###############################################################
#  Generated by:      Cadence Innovus 23.15-s106_1
#  OS:                Linux x86_64(Host ID ASIC-vm)
#  Generated on:      Fri Nov 14 15:30:56 2025
#  Design:            matmul_sync
#  Command:           write_lef_abstract -exclude_obs_layers $top_layer -stripe_pins -pg_pin_layers 10 [file join models [get_db flow_report_name] [get_db [current_design] .name].lef]
###############################################################

VERSION 5.8 ;

BUSBITCHARS "[]" ;
DIVIDERCHAR "/" ;

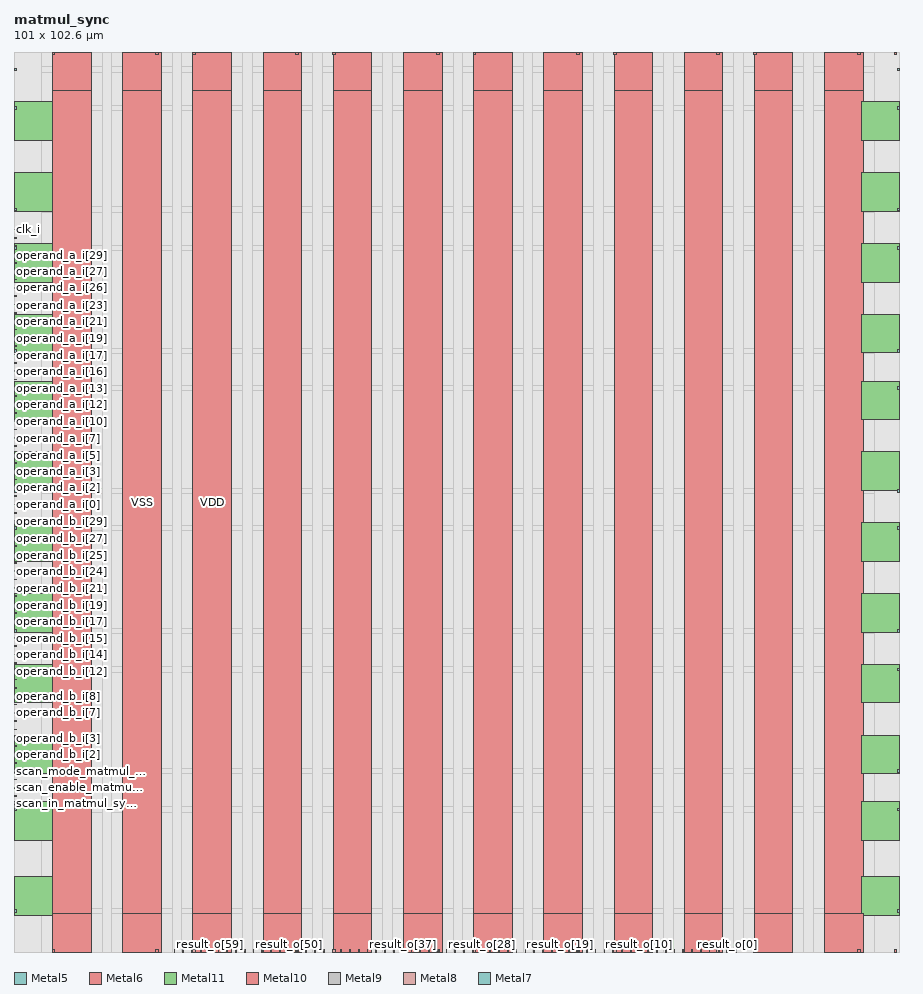
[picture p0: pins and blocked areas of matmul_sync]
MACRO matmul_sync
  CLASS BLOCK ;
  SIZE 101.000000 BY 102.600000 ;
  FOREIGN matmul_sync 0.000000 0.000000 ;
  ORIGIN 0 0 ;
  SYMMETRY X Y R90 ;
  PIN clk_i
    DIRECTION INPUT ;
    USE SIGNAL ;
    ANTENNAPARTIALMETALAREA 0.99075 LAYER Metal5  ;
    ANTENNAPARTIALMETALSIDEAREA 3.5514 LAYER Metal5  ;
    ANTENNAMODEL OXIDE1 ;
    ANTENNAGATEAREA 0.1755 LAYER Metal5  ;
    ANTENNAMAXAREACAR 6.54359 LAYER Metal5  ;
    ANTENNAMAXSIDEAREACAR 25.1726 LAYER Metal5  ;
    ANTENNAMAXCUTCAR 0.451282 LAYER Via5  ;
    PORT
      LAYER Metal5 ;
        RECT 0.000000 82.325000 0.250000 82.405000 ;
    END
  END clk_i
  PIN rst_ni
    DIRECTION INPUT ;
    USE SIGNAL ;
    ANTENNAPARTIALMETALAREA 0.3474 LAYER Metal5  ;
    ANTENNAPARTIALMETALSIDEAREA 1.5318 LAYER Metal5  ;
    ANTENNAMODEL OXIDE1 ;
    ANTENNAGATEAREA 0.0162 LAYER Metal5  ;
    ANTENNAMAXAREACAR 27.3673 LAYER Metal5  ;
    ANTENNAMAXSIDEAREACAR 129.926 LAYER Metal5  ;
    ANTENNAMAXCUTCAR 3.60802 LAYER Via5  ;
    PORT
      LAYER Metal5 ;
        RECT 0.000000 81.375000 0.250000 81.455000 ;
    END
  END rst_ni
  PIN operand_a_i[31]
    DIRECTION INPUT ;
    USE SIGNAL ;
    ANTENNAPARTIALMETALAREA 1.433 LAYER Metal5  ;
    ANTENNAPARTIALMETALSIDEAREA 6.417 LAYER Metal5  ;
    ANTENNAMODEL OXIDE1 ;
    ANTENNAGATEAREA 0.02925 LAYER Metal5  ;
    ANTENNAMAXAREACAR 71.5282 LAYER Metal5  ;
    ANTENNAMAXSIDEAREACAR 326.482 LAYER Metal5  ;
    ANTENNAMAXCUTCAR 2.89915 LAYER Via5  ;
    PORT
      LAYER Metal5 ;
        RECT 0.000000 80.425000 0.250000 80.505000 ;
    END
  END operand_a_i[31]
  PIN operand_a_i[30]
    DIRECTION INPUT ;
    USE SIGNAL ;
    ANTENNAPARTIALMETALAREA 0.9234 LAYER Metal5  ;
    ANTENNAPARTIALMETALSIDEAREA 4.1238 LAYER Metal5  ;
    ANTENNAMODEL OXIDE1 ;
    ANTENNAGATEAREA 0.02925 LAYER Metal5  ;
    ANTENNAMAXAREACAR 39.8085 LAYER Metal5  ;
    ANTENNAMAXSIDEAREACAR 184.821 LAYER Metal5  ;
    ANTENNAMAXCUTCAR 2.89915 LAYER Via5  ;
    PORT
      LAYER Metal5 ;
        RECT 0.000000 79.475000 0.250000 79.555000 ;
    END
  END operand_a_i[30]
  PIN operand_a_i[29]
    DIRECTION INPUT ;
    USE SIGNAL ;
    ANTENNAPARTIALMETALAREA 1.5314 LAYER Metal5  ;
    ANTENNAPARTIALMETALSIDEAREA 6.8598 LAYER Metal5  ;
    ANTENNAMODEL OXIDE1 ;
    ANTENNAGATEAREA 0.02925 LAYER Metal5  ;
    ANTENNAMAXAREACAR 61.135 LAYER Metal5  ;
    ANTENNAMAXSIDEAREACAR 279.713 LAYER Metal5  ;
    ANTENNAMAXCUTCAR 2.89915 LAYER Via5  ;
    PORT
      LAYER Metal5 ;
        RECT 0.000000 78.525000 0.250000 78.605000 ;
    END
  END operand_a_i[29]
  PIN operand_a_i[28]
    DIRECTION INPUT ;
    USE SIGNAL ;
    ANTENNAPARTIALMETALAREA 0.9874 LAYER Metal5  ;
    ANTENNAPARTIALMETALSIDEAREA 4.4118 LAYER Metal5  ;
    ANTENNAMODEL OXIDE1 ;
    ANTENNAGATEAREA 0.02925 LAYER Metal5  ;
    ANTENNAMAXAREACAR 41.4769 LAYER Metal5  ;
    ANTENNAMAXSIDEAREACAR 192.328 LAYER Metal5  ;
    ANTENNAMAXCUTCAR 2.89915 LAYER Via5  ;
    PORT
      LAYER Metal5 ;
        RECT 0.000000 77.575000 0.250000 77.655000 ;
    END
  END operand_a_i[28]
  PIN operand_a_i[27]
    DIRECTION INPUT ;
    USE SIGNAL ;
    ANTENNAPARTIALMETALAREA 1.6274 LAYER Metal5  ;
    ANTENNAPARTIALMETALSIDEAREA 7.2918 LAYER Metal5  ;
    ANTENNAMODEL OXIDE1 ;
    ANTENNAGATEAREA 0.02925 LAYER Metal5  ;
    ANTENNAMAXAREACAR 72.9949 LAYER Metal5  ;
    ANTENNAMAXSIDEAREACAR 331.056 LAYER Metal5  ;
    ANTENNAMAXCUTCAR 2.98462 LAYER Via5  ;
    PORT
      LAYER Metal5 ;
        RECT 0.000000 76.625000 0.250000 76.705000 ;
    END
  END operand_a_i[27]
  PIN operand_a_i[26]
    DIRECTION INPUT ;
    USE SIGNAL ;
    ANTENNAPARTIALMETALAREA 1.7164 LAYER Metal5  ;
    ANTENNAPARTIALMETALSIDEAREA 7.7238 LAYER Metal5  ;
    ANTENNAMODEL OXIDE1 ;
    ANTENNAGATEAREA 0.02925 LAYER Metal5  ;
    ANTENNAMAXAREACAR 64.2872 LAYER Metal5  ;
    ANTENNAMAXSIDEAREACAR 294.974 LAYER Metal5  ;
    ANTENNAMAXCUTCAR 2.89915 LAYER Via5  ;
    PORT
      LAYER Metal5 ;
        RECT 0.000000 75.675000 0.250000 75.755000 ;
    END
  END operand_a_i[26]
  PIN operand_a_i[25]
    DIRECTION INPUT ;
    USE SIGNAL ;
    ANTENNAPARTIALMETALAREA 0.8364 LAYER Metal5  ;
    ANTENNAPARTIALMETALSIDEAREA 3.7638 LAYER Metal5  ;
    ANTENNAMODEL OXIDE1 ;
    ANTENNAGATEAREA 0.02925 LAYER Metal5  ;
    ANTENNAMAXAREACAR 34.1744 LAYER Metal5  ;
    ANTENNAMAXSIDEAREACAR 160.328 LAYER Metal5  ;
    ANTENNAMAXCUTCAR 2.70769 LAYER Via5  ;
    PORT
      LAYER Metal5 ;
        RECT 0.000000 74.725000 0.250000 74.805000 ;
    END
  END operand_a_i[25]
  PIN operand_a_i[24]
    DIRECTION INPUT ;
    USE SIGNAL ;
    ANTENNAPARTIALMETALAREA 0.9554 LAYER Metal5  ;
    ANTENNAPARTIALMETALSIDEAREA 4.2678 LAYER Metal5  ;
    ANTENNAMODEL OXIDE1 ;
    ANTENNAGATEAREA 0.02925 LAYER Metal5  ;
    ANTENNAMAXAREACAR 39.3436 LAYER Metal5  ;
    ANTENNAMAXSIDEAREACAR 182.728 LAYER Metal5  ;
    ANTENNAMAXCUTCAR 2.89915 LAYER Via5  ;
    PORT
      LAYER Metal5 ;
        RECT 0.000000 73.775000 0.250000 73.855000 ;
    END
  END operand_a_i[24]
  PIN operand_a_i[23]
    DIRECTION INPUT ;
    USE SIGNAL ;
    ANTENNAPARTIALMETALAREA 0.7932 LAYER Metal5  ;
    ANTENNAPARTIALMETALSIDEAREA 3.5694 LAYER Metal5  ;
    ANTENNAMODEL OXIDE1 ;
    ANTENNAGATEAREA 0.02925 LAYER Metal5  ;
    ANTENNAMAXAREACAR 47.8974 LAYER Metal5  ;
    ANTENNAMAXSIDEAREACAR 220.144 LAYER Metal5  ;
    ANTENNAMAXCUTCAR 2.73162 LAYER Via5  ;
    PORT
      LAYER Metal5 ;
        RECT 0.000000 72.825000 0.250000 72.905000 ;
    END
  END operand_a_i[23]
  PIN operand_a_i[22]
    DIRECTION INPUT ;
    USE SIGNAL ;
    ANTENNAPARTIALMETALAREA 1.7386 LAYER Metal5  ;
    ANTENNAPARTIALMETALSIDEAREA 7.7922 LAYER Metal5  ;
    ANTENNAMODEL OXIDE1 ;
    ANTENNAGATEAREA 0.02925 LAYER Metal5  ;
    ANTENNAMAXAREACAR 69.2376 LAYER Metal5  ;
    ANTENNAMAXSIDEAREACAR 317.251 LAYER Metal5  ;
    ANTENNAMAXCUTCAR 2.89915 LAYER Via5  ;
    PORT
      LAYER Metal5 ;
        RECT 0.000000 71.875000 0.250000 71.955000 ;
    END
  END operand_a_i[22]
  PIN operand_a_i[21]
    DIRECTION INPUT ;
    USE SIGNAL ;
    ANTENNAPARTIALMETALAREA 1.4034 LAYER Metal5  ;
    ANTENNAPARTIALMETALSIDEAREA 6.2838 LAYER Metal5  ;
    ANTENNAMODEL OXIDE1 ;
    ANTENNAGATEAREA 0.02925 LAYER Metal5  ;
    ANTENNAMAXAREACAR 69.9145 LAYER Metal5  ;
    ANTENNAMAXSIDEAREACAR 319.221 LAYER Metal5  ;
    ANTENNAMAXCUTCAR 2.89915 LAYER Via5  ;
    PORT
      LAYER Metal5 ;
        RECT 0.000000 70.925000 0.250000 71.005000 ;
    END
  END operand_a_i[21]
  PIN operand_a_i[20]
    DIRECTION INPUT ;
    USE SIGNAL ;
    ANTENNAPARTIALMETALAREA 1.8602 LAYER Metal5  ;
    ANTENNAPARTIALMETALSIDEAREA 8.3394 LAYER Metal5  ;
    ANTENNAMODEL OXIDE1 ;
    ANTENNAGATEAREA 0.02925 LAYER Metal5  ;
    ANTENNAMAXAREACAR 68.0615 LAYER Metal5  ;
    ANTENNAMAXSIDEAREACAR 311.959 LAYER Metal5  ;
    ANTENNAMAXCUTCAR 2.89915 LAYER Via5  ;
    PORT
      LAYER Metal5 ;
        RECT 0.000000 69.975000 0.250000 70.055000 ;
    END
  END operand_a_i[20]
  PIN operand_a_i[19]
    DIRECTION INPUT ;
    USE SIGNAL ;
    ANTENNAPARTIALMETALAREA 1.5434 LAYER Metal5  ;
    ANTENNAPARTIALMETALSIDEAREA 6.9138 LAYER Metal5  ;
    ANTENNAMODEL OXIDE1 ;
    ANTENNAGATEAREA 0.02925 LAYER Metal5  ;
    ANTENNAMAXAREACAR 72.5128 LAYER Metal5  ;
    ANTENNAMAXSIDEAREACAR 330.913 LAYER Metal5  ;
    ANTENNAMAXCUTCAR 2.89915 LAYER Via5  ;
    PORT
      LAYER Metal5 ;
        RECT 0.000000 69.025000 0.250000 69.105000 ;
    END
  END operand_a_i[19]
  PIN operand_a_i[18]
    DIRECTION INPUT ;
    USE SIGNAL ;
    ANTENNAPARTIALMETALAREA 1.4026 LAYER Metal5  ;
    ANTENNAPARTIALMETALSIDEAREA 6.2802 LAYER Metal5  ;
    ANTENNAMODEL OXIDE1 ;
    ANTENNAGATEAREA 0.02925 LAYER Metal5  ;
    ANTENNAMAXAREACAR 70.4342 LAYER Metal5  ;
    ANTENNAMAXSIDEAREACAR 321.559 LAYER Metal5  ;
    ANTENNAMAXCUTCAR 2.89915 LAYER Via5  ;
    PORT
      LAYER Metal5 ;
        RECT 0.000000 68.075000 0.250000 68.155000 ;
    END
  END operand_a_i[18]
  PIN operand_a_i[17]
    DIRECTION INPUT ;
    USE SIGNAL ;
    ANTENNAPARTIALMETALAREA 0.8594 LAYER Metal5  ;
    ANTENNAPARTIALMETALSIDEAREA 3.8358 LAYER Metal5  ;
    ANTENNAMODEL OXIDE1 ;
    ANTENNAGATEAREA 0.02925 LAYER Metal5  ;
    ANTENNAMAXAREACAR 49.9692 LAYER Metal5  ;
    ANTENNAMAXSIDEAREACAR 231.405 LAYER Metal5  ;
    ANTENNAMAXCUTCAR 2.54017 LAYER Via5  ;
    PORT
      LAYER Metal5 ;
        RECT 0.000000 67.125000 0.250000 67.205000 ;
    END
  END operand_a_i[17]
  PIN operand_a_i[16]
    DIRECTION INPUT ;
    USE SIGNAL ;
    ANTENNAPARTIALMETALAREA 0.1874 LAYER Metal5  ;
    ANTENNAPARTIALMETALSIDEAREA 0.8118 LAYER Metal5  ;
    ANTENNAMODEL OXIDE1 ;
    ANTENNAGATEAREA 0.02925 LAYER Metal5  ;
    ANTENNAMAXAREACAR 39.8291 LAYER Metal5  ;
    ANTENNAMAXSIDEAREACAR 183.836 LAYER Metal5  ;
    ANTENNAMAXCUTCAR 2.89915 LAYER Via5  ;
    PORT
      LAYER Metal5 ;
        RECT 0.000000 66.175000 0.250000 66.255000 ;
    END
  END operand_a_i[16]
  PIN operand_a_i[15]
    DIRECTION INPUT ;
    USE SIGNAL ;
    ANTENNAPARTIALMETALAREA 0.8684 LAYER Metal5  ;
    ANTENNAPARTIALMETALSIDEAREA 3.9078 LAYER Metal5  ;
    ANTENNAMODEL OXIDE1 ;
    ANTENNAGATEAREA 0.02925 LAYER Metal5  ;
    ANTENNAMAXAREACAR 50.5573 LAYER Metal5  ;
    ANTENNAMAXSIDEAREACAR 233.19 LAYER Metal5  ;
    ANTENNAMAXCUTCAR 2.89915 LAYER Via5  ;
    PORT
      LAYER Metal5 ;
        RECT 0.000000 65.225000 0.250000 65.305000 ;
    END
  END operand_a_i[15]
  PIN operand_a_i[14]
    DIRECTION INPUT ;
    USE SIGNAL ;
    ANTENNAPARTIALMETALAREA 1.4826 LAYER Metal5  ;
    ANTENNAPARTIALMETALSIDEAREA 6.6402 LAYER Metal5  ;
    ANTENNAMODEL OXIDE1 ;
    ANTENNAGATEAREA 0.02925 LAYER Metal5  ;
    ANTENNAMAXAREACAR 92.5607 LAYER Metal5  ;
    ANTENNAMAXSIDEAREACAR 421.128 LAYER Metal5  ;
    ANTENNAMAXCUTCAR 2.89915 LAYER Via5  ;
    PORT
      LAYER Metal5 ;
        RECT 0.000000 64.275000 0.250000 64.355000 ;
    END
  END operand_a_i[14]
  PIN operand_a_i[13]
    DIRECTION INPUT ;
    USE SIGNAL ;
    ANTENNAPARTIALMETALAREA 1.5618 LAYER Metal5  ;
    ANTENNAPARTIALMETALSIDEAREA 6.9966 LAYER Metal5  ;
    ANTENNAMODEL OXIDE1 ;
    ANTENNAGATEAREA 0.02925 LAYER Metal5  ;
    ANTENNAMAXAREACAR 85.9692 LAYER Metal5  ;
    ANTENNAMAXSIDEAREACAR 391.467 LAYER Metal5  ;
    ANTENNAMAXCUTCAR 2.89915 LAYER Via5  ;
    PORT
      LAYER Metal5 ;
        RECT 0.000000 63.325000 0.250000 63.405000 ;
    END
  END operand_a_i[13]
  PIN operand_a_i[12]
    DIRECTION INPUT ;
    USE SIGNAL ;
    ANTENNAPARTIALMETALAREA 0.2354 LAYER Metal5  ;
    ANTENNAPARTIALMETALSIDEAREA 1.0278 LAYER Metal5  ;
    ANTENNAMODEL OXIDE1 ;
    ANTENNAGATEAREA 0.02925 LAYER Metal5  ;
    ANTENNAMAXAREACAR 51.9179 LAYER Metal5  ;
    ANTENNAMAXSIDEAREACAR 238.236 LAYER Metal5  ;
    ANTENNAMAXCUTCAR 2.89915 LAYER Via5  ;
    PORT
      LAYER Metal5 ;
        RECT 0.000000 62.375000 0.250000 62.455000 ;
    END
  END operand_a_i[12]
  PIN operand_a_i[11]
    DIRECTION INPUT ;
    USE SIGNAL ;
    ANTENNAPARTIALMETALAREA 0.8274 LAYER Metal5  ;
    ANTENNAPARTIALMETALSIDEAREA 3.6918 LAYER Metal5  ;
    ANTENNAMODEL OXIDE1 ;
    ANTENNAGATEAREA 0.02925 LAYER Metal5  ;
    ANTENNAMAXAREACAR 50.7692 LAYER Metal5  ;
    ANTENNAMAXSIDEAREACAR 233.067 LAYER Metal5  ;
    ANTENNAMAXCUTCAR 2.89915 LAYER Via5  ;
    PORT
      LAYER Metal5 ;
        RECT 0.000000 61.425000 0.250000 61.505000 ;
    END
  END operand_a_i[11]
  PIN operand_a_i[10]
    DIRECTION INPUT ;
    USE SIGNAL ;
    ANTENNAPARTIALMETALAREA 0.8892 LAYER Metal5  ;
    ANTENNAPARTIALMETALSIDEAREA 4.0014 LAYER Metal5  ;
    ANTENNAMODEL OXIDE1 ;
    ANTENNAGATEAREA 0.02925 LAYER Metal5  ;
    ANTENNAMAXAREACAR 38.9949 LAYER Metal5  ;
    ANTENNAMAXSIDEAREACAR 180.082 LAYER Metal5  ;
    ANTENNAMAXCUTCAR 2.73162 LAYER Via5  ;
    PORT
      LAYER Metal5 ;
        RECT 0.000000 60.475000 0.250000 60.555000 ;
    END
  END operand_a_i[10]
  PIN operand_a_i[9]
    DIRECTION INPUT ;
    USE SIGNAL ;
    ANTENNAPARTIALMETALAREA 1.3714 LAYER Metal5  ;
    ANTENNAPARTIALMETALSIDEAREA 6.1398 LAYER Metal5  ;
    ANTENNAMODEL OXIDE1 ;
    ANTENNAGATEAREA 0.02925 LAYER Metal5  ;
    ANTENNAMAXAREACAR 59.6581 LAYER Metal5  ;
    ANTENNAMAXSIDEAREACAR 273.067 LAYER Metal5  ;
    ANTENNAMAXCUTCAR 2.89915 LAYER Via5  ;
    PORT
      LAYER Metal5 ;
        RECT 0.000000 59.525000 0.250000 59.605000 ;
    END
  END operand_a_i[9]
  PIN operand_a_i[8]
    DIRECTION INPUT ;
    USE SIGNAL ;
    ANTENNAPARTIALMETALAREA 1.9116 LAYER Metal5  ;
    ANTENNAPARTIALMETALSIDEAREA 8.6022 LAYER Metal5  ;
    ANTENNAMODEL OXIDE1 ;
    ANTENNAGATEAREA 0.02925 LAYER Metal5  ;
    ANTENNAMAXAREACAR 71.7744 LAYER Metal5  ;
    ANTENNAMAXSIDEAREACAR 327.59 LAYER Metal5  ;
    ANTENNAMAXCUTCAR 2.89915 LAYER Via5  ;
    PORT
      LAYER Metal5 ;
        RECT 0.000000 58.575000 0.250000 58.655000 ;
    END
  END operand_a_i[8]
  PIN operand_a_i[7]
    DIRECTION INPUT ;
    USE SIGNAL ;
    ANTENNAPARTIALMETALAREA 2.3154 LAYER Metal5  ;
    ANTENNAPARTIALMETALSIDEAREA 10.3878 LAYER Metal5  ;
    ANTENNAMODEL OXIDE1 ;
    ANTENNAGATEAREA 0.02925 LAYER Metal5  ;
    ANTENNAMAXAREACAR 91.0359 LAYER Metal5  ;
    ANTENNAMAXSIDEAREACAR 415.344 LAYER Metal5  ;
    ANTENNAMAXCUTCAR 2.89915 LAYER Via5  ;
    PORT
      LAYER Metal5 ;
        RECT 0.000000 57.625000 0.250000 57.705000 ;
    END
  END operand_a_i[7]
  PIN operand_a_i[6]
    DIRECTION INPUT ;
    USE SIGNAL ;
    ANTENNAPARTIALMETALAREA 2.2034 LAYER Metal5  ;
    ANTENNAPARTIALMETALSIDEAREA 9.8838 LAYER Metal5  ;
    ANTENNAMODEL OXIDE1 ;
    ANTENNAGATEAREA 0.02925 LAYER Metal5  ;
    ANTENNAMAXAREACAR 96.7453 LAYER Metal5  ;
    ANTENNAMAXSIDEAREACAR 439.959 LAYER Metal5  ;
    ANTENNAMAXCUTCAR 2.89915 LAYER Via5  ;
    PORT
      LAYER Metal5 ;
        RECT 0.000000 56.675000 0.250000 56.755000 ;
    END
  END operand_a_i[6]
  PIN operand_a_i[5]
    DIRECTION INPUT ;
    USE SIGNAL ;
    ANTENNAPARTIALMETALAREA 1.5634 LAYER Metal5  ;
    ANTENNAPARTIALMETALSIDEAREA 7.0038 LAYER Metal5  ;
    ANTENNAMODEL OXIDE1 ;
    ANTENNAGATEAREA 0.02925 LAYER Metal5  ;
    ANTENNAMAXAREACAR 80.9709 LAYER Metal5  ;
    ANTENNAMAXSIDEAREACAR 370.051 LAYER Metal5  ;
    ANTENNAMAXCUTCAR 2.89915 LAYER Via5  ;
    PORT
      LAYER Metal5 ;
        RECT 0.000000 55.725000 0.250000 55.805000 ;
    END
  END operand_a_i[5]
  PIN operand_a_i[4]
    DIRECTION INPUT ;
    USE SIGNAL ;
    ANTENNAPARTIALMETALAREA 2.1066 LAYER Metal5  ;
    ANTENNAPARTIALMETALSIDEAREA 9.4482 LAYER Metal5  ;
    ANTENNAMODEL OXIDE1 ;
    ANTENNAGATEAREA 0.02925 LAYER Metal5  ;
    ANTENNAMAXAREACAR 85.641 LAYER Metal5  ;
    ANTENNAMAXSIDEAREACAR 389.99 LAYER Metal5  ;
    ANTENNAMAXCUTCAR 2.89915 LAYER Via5  ;
    PORT
      LAYER Metal5 ;
        RECT 0.000000 54.775000 0.250000 54.855000 ;
    END
  END operand_a_i[4]
  PIN operand_a_i[3]
    DIRECTION INPUT ;
    USE SIGNAL ;
    ANTENNAPARTIALMETALAREA 2.0242 LAYER Metal5  ;
    ANTENNAPARTIALMETALSIDEAREA 9.0774 LAYER Metal5  ;
    ANTENNAMODEL OXIDE1 ;
    ANTENNAGATEAREA 0.02925 LAYER Metal5  ;
    ANTENNAMAXAREACAR 79.2308 LAYER Metal5  ;
    ANTENNAMAXSIDEAREACAR 359.118 LAYER Metal5  ;
    ANTENNAMAXCUTCAR 2.98462 LAYER Via5  ;
    PORT
      LAYER Metal5 ;
        RECT 0.000000 53.825000 0.250000 53.905000 ;
    END
  END operand_a_i[3]
  PIN operand_a_i[2]
    DIRECTION INPUT ;
    USE SIGNAL ;
    ANTENNAPARTIALMETALAREA 2.0242 LAYER Metal5  ;
    ANTENNAPARTIALMETALSIDEAREA 9.0774 LAYER Metal5  ;
    ANTENNAMODEL OXIDE1 ;
    ANTENNAGATEAREA 0.02925 LAYER Metal5  ;
    ANTENNAMAXAREACAR 77.135 LAYER Metal5  ;
    ANTENNAMAXSIDEAREACAR 351.713 LAYER Metal5  ;
    ANTENNAMAXCUTCAR 2.89915 LAYER Via5  ;
    PORT
      LAYER Metal5 ;
        RECT 0.000000 52.875000 0.250000 52.955000 ;
    END
  END operand_a_i[2]
  PIN operand_a_i[1]
    DIRECTION INPUT ;
    USE SIGNAL ;
    ANTENNAPARTIALMETALAREA 1.4756 LAYER Metal5  ;
    ANTENNAPARTIALMETALSIDEAREA 6.6402 LAYER Metal5  ;
    ANTENNAMODEL OXIDE1 ;
    ANTENNAGATEAREA 0.02925 LAYER Metal5  ;
    ANTENNAMAXAREACAR 55.0291 LAYER Metal5  ;
    ANTENNAMAXSIDEAREACAR 254.174 LAYER Metal5  ;
    ANTENNAMAXCUTCAR 2.54017 LAYER Via5  ;
    PORT
      LAYER Metal5 ;
        RECT 0.000000 51.925000 0.250000 52.005000 ;
    END
  END operand_a_i[1]
  PIN operand_a_i[0]
    DIRECTION INPUT ;
    USE SIGNAL ;
    ANTENNAPARTIALMETALAREA 0.1874 LAYER Metal5  ;
    ANTENNAPARTIALMETALSIDEAREA 0.8118 LAYER Metal5  ;
    ANTENNAMODEL OXIDE1 ;
    ANTENNAGATEAREA 0.02925 LAYER Metal5  ;
    ANTENNAMAXAREACAR 41.388 LAYER Metal5  ;
    ANTENNAMAXSIDEAREACAR 190.851 LAYER Metal5  ;
    ANTENNAMAXCUTCAR 2.89915 LAYER Via5  ;
    PORT
      LAYER Metal5 ;
        RECT 0.000000 50.975000 0.250000 51.055000 ;
    END
  END operand_a_i[0]
  PIN operand_b_i[31]
    DIRECTION INPUT ;
    USE SIGNAL ;
    ANTENNAPARTIALMETALAREA 0.9874 LAYER Metal5  ;
    ANTENNAPARTIALMETALSIDEAREA 4.4118 LAYER Metal5  ;
    ANTENNAMODEL OXIDE1 ;
    ANTENNAGATEAREA 0.02925 LAYER Metal5  ;
    ANTENNAMAXAREACAR 92.6154 LAYER Metal5  ;
    ANTENNAMAXSIDEAREACAR 421.374 LAYER Metal5  ;
    ANTENNAMAXCUTCAR 2.89915 LAYER Via5  ;
    PORT
      LAYER Metal5 ;
        RECT 0.000000 50.025000 0.250000 50.105000 ;
    END
  END operand_b_i[31]
  PIN operand_b_i[30]
    DIRECTION INPUT ;
    USE SIGNAL ;
    ANTENNAPARTIALMETALAREA 0.9074 LAYER Metal5  ;
    ANTENNAPARTIALMETALSIDEAREA 4.0518 LAYER Metal5  ;
    ANTENNAMODEL OXIDE1 ;
    ANTENNAGATEAREA 0.02925 LAYER Metal5  ;
    ANTENNAMAXAREACAR 39.6444 LAYER Metal5  ;
    ANTENNAMAXSIDEAREACAR 184.082 LAYER Metal5  ;
    ANTENNAMAXCUTCAR 2.89915 LAYER Via5  ;
    PORT
      LAYER Metal5 ;
        RECT 0.000000 49.075000 0.250000 49.155000 ;
    END
  END operand_b_i[30]
  PIN operand_b_i[29]
    DIRECTION INPUT ;
    USE SIGNAL ;
    ANTENNAPARTIALMETALAREA 0.2354 LAYER Metal5  ;
    ANTENNAPARTIALMETALSIDEAREA 1.0278 LAYER Metal5  ;
    ANTENNAMODEL OXIDE1 ;
    ANTENNAGATEAREA 0.02925 LAYER Metal5  ;
    ANTENNAMAXAREACAR 45.0256 LAYER Metal5  ;
    ANTENNAMAXSIDEAREACAR 207.221 LAYER Metal5  ;
    ANTENNAMAXCUTCAR 2.89915 LAYER Via5  ;
    PORT
      LAYER Metal5 ;
        RECT 0.000000 48.125000 0.250000 48.205000 ;
    END
  END operand_b_i[29]
  PIN operand_b_i[28]
    DIRECTION INPUT ;
    USE SIGNAL ;
    ANTENNAPARTIALMETALAREA 1.5778 LAYER Metal5  ;
    ANTENNAPARTIALMETALSIDEAREA 7.0686 LAYER Metal5  ;
    ANTENNAMODEL OXIDE1 ;
    ANTENNAGATEAREA 0.02925 LAYER Metal5  ;
    ANTENNAMAXAREACAR 98.5846 LAYER Metal5  ;
    ANTENNAMAXSIDEAREACAR 449.313 LAYER Metal5  ;
    ANTENNAMAXCUTCAR 2.89915 LAYER Via5  ;
    PORT
      LAYER Metal5 ;
        RECT 0.000000 47.175000 0.250000 47.255000 ;
    END
  END operand_b_i[28]
  PIN operand_b_i[27]
    DIRECTION INPUT ;
    USE SIGNAL ;
    ANTENNAPARTIALMETALAREA 1.6266 LAYER Metal5  ;
    ANTENNAPARTIALMETALSIDEAREA 7.2882 LAYER Metal5  ;
    ANTENNAMODEL OXIDE1 ;
    ANTENNAGATEAREA 0.02925 LAYER Metal5  ;
    ANTENNAMAXAREACAR 64.0615 LAYER Metal5  ;
    ANTENNAMAXSIDEAREACAR 292.882 LAYER Metal5  ;
    ANTENNAMAXCUTCAR 2.89915 LAYER Via5  ;
    PORT
      LAYER Metal5 ;
        RECT 0.000000 46.225000 0.250000 46.305000 ;
    END
  END operand_b_i[27]
  PIN operand_b_i[26]
    DIRECTION INPUT ;
    USE SIGNAL ;
    ANTENNAPARTIALMETALAREA 1.9932 LAYER Metal5  ;
    ANTENNAPARTIALMETALSIDEAREA 8.9694 LAYER Metal5  ;
    ANTENNAMODEL OXIDE1 ;
    ANTENNAGATEAREA 0.02925 LAYER Metal5  ;
    ANTENNAMAXAREACAR 88.4718 LAYER Metal5  ;
    ANTENNAMAXSIDEAREACAR 402.728 LAYER Metal5  ;
    ANTENNAMAXCUTCAR 2.73162 LAYER Via5  ;
    PORT
      LAYER Metal5 ;
        RECT 0.000000 45.275000 0.250000 45.355000 ;
    END
  END operand_b_i[26]
  PIN operand_b_i[25]
    DIRECTION INPUT ;
    USE SIGNAL ;
    ANTENNAPARTIALMETALAREA 1.6754 LAYER Metal5  ;
    ANTENNAPARTIALMETALSIDEAREA 7.5078 LAYER Metal5  ;
    ANTENNAMODEL OXIDE1 ;
    ANTENNAGATEAREA 0.02925 LAYER Metal5  ;
    ANTENNAMAXAREACAR 62.9197 LAYER Metal5  ;
    ANTENNAMAXSIDEAREACAR 288.821 LAYER Metal5  ;
    ANTENNAMAXCUTCAR 2.89915 LAYER Via5  ;
    PORT
      LAYER Metal5 ;
        RECT 0.000000 44.325000 0.250000 44.405000 ;
    END
  END operand_b_i[25]
  PIN operand_b_i[24]
    DIRECTION INPUT ;
    USE SIGNAL ;
    ANTENNAPARTIALMETALAREA 1.6754 LAYER Metal5  ;
    ANTENNAPARTIALMETALSIDEAREA 7.5078 LAYER Metal5  ;
    ANTENNAMODEL OXIDE1 ;
    ANTENNAGATEAREA 0.02925 LAYER Metal5  ;
    ANTENNAMAXAREACAR 64.9983 LAYER Metal5  ;
    ANTENNAMAXSIDEAREACAR 298.174 LAYER Metal5  ;
    ANTENNAMAXCUTCAR 2.89915 LAYER Via5  ;
    PORT
      LAYER Metal5 ;
        RECT 0.000000 43.375000 0.250000 43.455000 ;
    END
  END operand_b_i[24]
  PIN operand_b_i[23]
    DIRECTION INPUT ;
    USE SIGNAL ;
    ANTENNAPARTIALMETALAREA 0.6994 LAYER Metal5  ;
    ANTENNAPARTIALMETALSIDEAREA 3.1158 LAYER Metal5  ;
    ANTENNAMODEL OXIDE1 ;
    ANTENNAGATEAREA 0.02925 LAYER Metal5  ;
    ANTENNAMAXAREACAR 72.5675 LAYER Metal5  ;
    ANTENNAMAXSIDEAREACAR 331.159 LAYER Metal5  ;
    ANTENNAMAXCUTCAR 2.89915 LAYER Via5  ;
    PORT
      LAYER Metal5 ;
        RECT 0.000000 42.425000 0.250000 42.505000 ;
    END
  END operand_b_i[23]
  PIN operand_b_i[22]
    DIRECTION INPUT ;
    USE SIGNAL ;
    ANTENNAPARTIALMETALAREA 1.721 LAYER Metal5  ;
    ANTENNAPARTIALMETALSIDEAREA 7.713 LAYER Metal5  ;
    ANTENNAMODEL OXIDE1 ;
    ANTENNAGATEAREA 0.02925 LAYER Metal5  ;
    ANTENNAMAXAREACAR 64.4786 LAYER Metal5  ;
    ANTENNAMAXSIDEAREACAR 295.836 LAYER Metal5  ;
    ANTENNAMAXCUTCAR 2.89915 LAYER Via5  ;
    PORT
      LAYER Metal5 ;
        RECT 0.000000 41.475000 0.250000 41.555000 ;
    END
  END operand_b_i[22]
  PIN operand_b_i[21]
    DIRECTION INPUT ;
    USE SIGNAL ;
    ANTENNAPARTIALMETALAREA 1.6898 LAYER Metal5  ;
    ANTENNAPARTIALMETALSIDEAREA 7.5726 LAYER Metal5  ;
    ANTENNAMODEL OXIDE1 ;
    ANTENNAGATEAREA 0.02925 LAYER Metal5  ;
    ANTENNAMAXAREACAR 66.0103 LAYER Metal5  ;
    ANTENNAMAXSIDEAREACAR 302.728 LAYER Metal5  ;
    ANTENNAMAXCUTCAR 2.89915 LAYER Via5  ;
    PORT
      LAYER Metal5 ;
        RECT 0.000000 40.525000 0.250000 40.605000 ;
    END
  END operand_b_i[21]
  PIN operand_b_i[20]
    DIRECTION INPUT ;
    USE SIGNAL ;
    ANTENNAPARTIALMETALAREA 0.9394 LAYER Metal5  ;
    ANTENNAPARTIALMETALSIDEAREA 4.1958 LAYER Metal5  ;
    ANTENNAMODEL OXIDE1 ;
    ANTENNAGATEAREA 0.02925 LAYER Metal5  ;
    ANTENNAMAXAREACAR 57.8872 LAYER Metal5  ;
    ANTENNAMAXSIDEAREACAR 266.174 LAYER Metal5  ;
    ANTENNAMAXCUTCAR 2.89915 LAYER Via5  ;
    PORT
      LAYER Metal5 ;
        RECT 0.000000 39.575000 0.250000 39.655000 ;
    END
  END operand_b_i[20]
  PIN operand_b_i[19]
    DIRECTION INPUT ;
    USE SIGNAL ;
    ANTENNAPARTIALMETALAREA 1.3874 LAYER Metal5  ;
    ANTENNAPARTIALMETALSIDEAREA 6.2118 LAYER Metal5  ;
    ANTENNAMODEL OXIDE1 ;
    ANTENNAGATEAREA 0.02925 LAYER Metal5  ;
    ANTENNAMAXAREACAR 66.1128 LAYER Metal5  ;
    ANTENNAMAXSIDEAREACAR 302.113 LAYER Metal5  ;
    ANTENNAMAXCUTCAR 2.89915 LAYER Via5  ;
    PORT
      LAYER Metal5 ;
        RECT 0.000000 38.625000 0.250000 38.705000 ;
    END
  END operand_b_i[19]
  PIN operand_b_i[18]
    DIRECTION INPUT ;
    USE SIGNAL ;
    ANTENNAPARTIALMETALAREA 1.6266 LAYER Metal5  ;
    ANTENNAPARTIALMETALSIDEAREA 7.2882 LAYER Metal5  ;
    ANTENNAMODEL OXIDE1 ;
    ANTENNAGATEAREA 0.02925 LAYER Metal5  ;
    ANTENNAMAXAREACAR 72.0821 LAYER Metal5  ;
    ANTENNAMAXSIDEAREACAR 330.051 LAYER Metal5  ;
    ANTENNAMAXCUTCAR 2.89915 LAYER Via5  ;
    PORT
      LAYER Metal5 ;
        RECT 0.000000 37.675000 0.250000 37.755000 ;
    END
  END operand_b_i[18]
  PIN operand_b_i[17]
    DIRECTION INPUT ;
    USE SIGNAL ;
    ANTENNAPARTIALMETALAREA 0.9386 LAYER Metal5  ;
    ANTENNAPARTIALMETALSIDEAREA 4.1922 LAYER Metal5  ;
    ANTENNAMODEL OXIDE1 ;
    ANTENNAGATEAREA 0.02925 LAYER Metal5  ;
    ANTENNAMAXAREACAR 37.7231 LAYER Metal5  ;
    ANTENNAMAXSIDEAREACAR 174.359 LAYER Metal5  ;
    ANTENNAMAXCUTCAR 2.89915 LAYER Via5  ;
    PORT
      LAYER Metal5 ;
        RECT 0.000000 36.725000 0.250000 36.805000 ;
    END
  END operand_b_i[17]
  PIN operand_b_i[16]
    DIRECTION INPUT ;
    USE SIGNAL ;
    ANTENNAPARTIALMETALAREA 0.1692 LAYER Metal5  ;
    ANTENNAPARTIALMETALSIDEAREA 0.7614 LAYER Metal5  ;
    ANTENNAMODEL OXIDE1 ;
    ANTENNAGATEAREA 0.02925 LAYER Metal5  ;
    ANTENNAMAXAREACAR 45.5179 LAYER Metal5  ;
    ANTENNAMAXSIDEAREACAR 209.436 LAYER Metal5  ;
    ANTENNAMAXCUTCAR 2.73162 LAYER Via5  ;
    PORT
      LAYER Metal5 ;
        RECT 0.000000 35.775000 0.250000 35.855000 ;
    END
  END operand_b_i[16]
  PIN operand_b_i[15]
    DIRECTION INPUT ;
    USE SIGNAL ;
    ANTENNAPARTIALMETALAREA 0.7474 LAYER Metal5  ;
    ANTENNAPARTIALMETALSIDEAREA 3.3318 LAYER Metal5  ;
    ANTENNAMODEL OXIDE1 ;
    ANTENNAGATEAREA 0.02925 LAYER Metal5  ;
    ANTENNAMAXAREACAR 93.094 LAYER Metal5  ;
    ANTENNAMAXSIDEAREACAR 424.39 LAYER Metal5  ;
    ANTENNAMAXCUTCAR 2.54017 LAYER Via5  ;
    PORT
      LAYER Metal5 ;
        RECT 0.000000 34.825000 0.250000 34.905000 ;
    END
  END operand_b_i[15]
  PIN operand_b_i[14]
    DIRECTION INPUT ;
    USE SIGNAL ;
    ANTENNAPARTIALMETALAREA 0.7954 LAYER Metal5  ;
    ANTENNAPARTIALMETALSIDEAREA 3.5478 LAYER Metal5  ;
    ANTENNAMODEL OXIDE1 ;
    ANTENNAGATEAREA 0.0162 LAYER Metal5  ;
    ANTENNAMAXAREACAR 162.963 LAYER Metal5  ;
    ANTENNAMAXSIDEAREACAR 745.148 LAYER Metal5  ;
    ANTENNAMAXCUTCAR 4.58642 LAYER Via5  ;
    PORT
      LAYER Metal5 ;
        RECT 0.000000 33.875000 0.250000 33.955000 ;
    END
  END operand_b_i[14]
  PIN operand_b_i[13]
    DIRECTION INPUT ;
    USE SIGNAL ;
    ANTENNAPARTIALMETALAREA 1.4674 LAYER Metal5  ;
    ANTENNAPARTIALMETALSIDEAREA 6.5718 LAYER Metal5  ;
    ANTENNAMODEL OXIDE1 ;
    ANTENNAGATEAREA 0.02925 LAYER Metal5  ;
    ANTENNAMAXAREACAR 103.501 LAYER Metal5  ;
    ANTENNAMAXSIDEAREACAR 470.359 LAYER Metal5  ;
    ANTENNAMAXCUTCAR 2.89915 LAYER Via5  ;
    PORT
      LAYER Metal5 ;
        RECT 0.000000 32.925000 0.250000 33.005000 ;
    END
  END operand_b_i[13]
  PIN operand_b_i[12]
    DIRECTION INPUT ;
    USE SIGNAL ;
    ANTENNAPARTIALMETALAREA 0.5476 LAYER Metal5  ;
    ANTENNAPARTIALMETALSIDEAREA 2.4642 LAYER Metal5  ;
    ANTENNAMODEL OXIDE1 ;
    ANTENNAGATEAREA 0.0162 LAYER Metal5  ;
    ANTENNAMAXAREACAR 121.185 LAYER Metal5  ;
    ANTENNAMAXSIDEAREACAR 557.148 LAYER Metal5  ;
    ANTENNAMAXCUTCAR 4.58642 LAYER Via5  ;
    PORT
      LAYER Metal5 ;
        RECT 0.000000 31.975000 0.250000 32.055000 ;
    END
  END operand_b_i[12]
  PIN operand_b_i[11]
    DIRECTION INPUT ;
    USE SIGNAL ;
    ANTENNAPARTIALMETALAREA 0.9074 LAYER Metal5  ;
    ANTENNAPARTIALMETALSIDEAREA 4.0518 LAYER Metal5  ;
    ANTENNAMODEL OXIDE1 ;
    ANTENNAGATEAREA 0.02925 LAYER Metal5  ;
    ANTENNAMAXAREACAR 76.3692 LAYER Metal5  ;
    ANTENNAMAXSIDEAREACAR 348.267 LAYER Metal5  ;
    ANTENNAMAXCUTCAR 2.89915 LAYER Via5  ;
    PORT
      LAYER Metal5 ;
        RECT 0.000000 31.025000 0.250000 31.105000 ;
    END
  END operand_b_i[11]
  PIN operand_b_i[10]
    DIRECTION INPUT ;
    USE SIGNAL ;
    ANTENNAPARTIALMETALAREA 0.9714 LAYER Metal5  ;
    ANTENNAPARTIALMETALSIDEAREA 4.3398 LAYER Metal5  ;
    ANTENNAMODEL OXIDE1 ;
    ANTENNAGATEAREA 0.02925 LAYER Metal5  ;
    ANTENNAMAXAREACAR 76.4786 LAYER Metal5  ;
    ANTENNAMAXSIDEAREACAR 348.759 LAYER Metal5  ;
    ANTENNAMAXCUTCAR 2.89915 LAYER Via5  ;
    PORT
      LAYER Metal5 ;
        RECT 0.000000 30.075000 0.250000 30.155000 ;
    END
  END operand_b_i[10]
  PIN operand_b_i[9]
    DIRECTION INPUT ;
    USE SIGNAL ;
    ANTENNAPARTIALMETALAREA 1.0506 LAYER Metal5  ;
    ANTENNAPARTIALMETALSIDEAREA 4.6962 LAYER Metal5  ;
    ANTENNAMODEL OXIDE1 ;
    ANTENNAGATEAREA 0.02925 LAYER Metal5  ;
    ANTENNAMAXAREACAR 78.2291 LAYER Metal5  ;
    ANTENNAMAXSIDEAREACAR 356.636 LAYER Metal5  ;
    ANTENNAMAXCUTCAR 2.89915 LAYER Via5  ;
    PORT
      LAYER Metal5 ;
        RECT 0.000000 29.125000 0.250000 29.205000 ;
    END
  END operand_b_i[9]
  PIN operand_b_i[8]
    DIRECTION INPUT ;
    USE SIGNAL ;
    ANTENNAPARTIALMETALAREA 1.0034 LAYER Metal5  ;
    ANTENNAPARTIALMETALSIDEAREA 4.4838 LAYER Metal5  ;
    ANTENNAMODEL OXIDE1 ;
    ANTENNAGATEAREA 0.02925 LAYER Metal5  ;
    ANTENNAMAXAREACAR 68.7385 LAYER Metal5  ;
    ANTENNAMAXSIDEAREACAR 313.928 LAYER Metal5  ;
    ANTENNAMAXCUTCAR 2.89915 LAYER Via5  ;
    PORT
      LAYER Metal5 ;
        RECT 0.000000 28.175000 0.250000 28.255000 ;
    END
  END operand_b_i[8]
  PIN operand_b_i[7]
    DIRECTION INPUT ;
    USE SIGNAL ;
    ANTENNAPARTIALMETALAREA 1.3874 LAYER Metal5  ;
    ANTENNAPARTIALMETALSIDEAREA 6.2118 LAYER Metal5  ;
    ANTENNAMODEL OXIDE1 ;
    ANTENNAGATEAREA 0.02925 LAYER Metal5  ;
    ANTENNAMAXAREACAR 57.641 LAYER Metal5  ;
    ANTENNAMAXSIDEAREACAR 263.897 LAYER Metal5  ;
    ANTENNAMAXCUTCAR 2.03419 LAYER Via5  ;
    PORT
      LAYER Metal5 ;
        RECT 0.000000 27.225000 0.250000 27.305000 ;
    END
  END operand_b_i[7]
  PIN operand_b_i[6]
    DIRECTION INPUT ;
    USE SIGNAL ;
    ANTENNAPARTIALMETALAREA 0.6116 LAYER Metal5  ;
    ANTENNAPARTIALMETALSIDEAREA 2.7522 LAYER Metal5  ;
    ANTENNAMODEL OXIDE1 ;
    ANTENNAGATEAREA 0.0162 LAYER Metal5  ;
    ANTENNAMAXAREACAR 46.716 LAYER Metal5  ;
    ANTENNAMAXSIDEAREACAR 222.037 LAYER Metal5  ;
    ANTENNAMAXCUTCAR 4.58642 LAYER Via5  ;
    PORT
      LAYER Metal5 ;
        RECT 0.000000 26.275000 0.250000 26.355000 ;
    END
  END operand_b_i[6]
  PIN operand_b_i[5]
    DIRECTION INPUT ;
    USE SIGNAL ;
    ANTENNAPARTIALMETALAREA 0.9644 LAYER Metal5  ;
    ANTENNAPARTIALMETALSIDEAREA 4.3398 LAYER Metal5  ;
    ANTENNAMODEL OXIDE1 ;
    ANTENNAGATEAREA 0.02925 LAYER Metal5  ;
    ANTENNAMAXAREACAR 44.9504 LAYER Metal5  ;
    ANTENNAMAXSIDEAREACAR 207.959 LAYER Metal5  ;
    ANTENNAMAXCUTCAR 2.89915 LAYER Via5  ;
    PORT
      LAYER Metal5 ;
        RECT 0.000000 25.325000 0.250000 25.405000 ;
    END
  END operand_b_i[5]
  PIN operand_b_i[4]
    DIRECTION INPUT ;
    USE SIGNAL ;
    ANTENNAPARTIALMETALAREA 0.5204 LAYER Metal5  ;
    ANTENNAPARTIALMETALSIDEAREA 2.3418 LAYER Metal5  ;
    ANTENNAMODEL OXIDE1 ;
    ANTENNAGATEAREA 0.0162 LAYER Metal5  ;
    ANTENNAMAXAREACAR 39.4568 LAYER Metal5  ;
    ANTENNAMAXSIDEAREACAR 189.37 LAYER Metal5  ;
    ANTENNAMAXCUTCAR 4.58642 LAYER Via5  ;
    PORT
      LAYER Metal5 ;
        RECT 0.000000 24.375000 0.250000 24.455000 ;
    END
  END operand_b_i[4]
  PIN operand_b_i[3]
    DIRECTION INPUT ;
    USE SIGNAL ;
    ANTENNAPARTIALMETALAREA 1.0026 LAYER Metal5  ;
    ANTENNAPARTIALMETALSIDEAREA 4.4802 LAYER Metal5  ;
    ANTENNAMODEL OXIDE1 ;
    ANTENNAGATEAREA 0.02925 LAYER Metal5  ;
    ANTENNAMAXAREACAR 38.7419 LAYER Metal5  ;
    ANTENNAMAXSIDEAREACAR 180.021 LAYER Metal5  ;
    ANTENNAMAXCUTCAR 2.89915 LAYER Via5  ;
    PORT
      LAYER Metal5 ;
        RECT 0.000000 23.425000 0.250000 23.505000 ;
    END
  END operand_b_i[3]
  PIN operand_b_i[2]
    DIRECTION INPUT ;
    USE SIGNAL ;
    ANTENNAPARTIALMETALAREA 0.8684 LAYER Metal5  ;
    ANTENNAPARTIALMETALSIDEAREA 3.9078 LAYER Metal5  ;
    ANTENNAMODEL OXIDE1 ;
    ANTENNAGATEAREA 0.02925 LAYER Metal5  ;
    ANTENNAMAXAREACAR 36.9915 LAYER Metal5  ;
    ANTENNAMAXSIDEAREACAR 172.144 LAYER Metal5  ;
    ANTENNAMAXCUTCAR 2.89915 LAYER Via5  ;
    PORT
      LAYER Metal5 ;
        RECT 0.000000 22.475000 0.250000 22.555000 ;
    END
  END operand_b_i[2]
  PIN operand_b_i[1]
    DIRECTION INPUT ;
    USE SIGNAL ;
    ANTENNAPARTIALMETALAREA 0.1692 LAYER Metal5  ;
    ANTENNAPARTIALMETALSIDEAREA 0.7614 LAYER Metal5  ;
    ANTENNAMODEL OXIDE1 ;
    ANTENNAGATEAREA 0.02925 LAYER Metal5  ;
    ANTENNAMAXAREACAR 39.788 LAYER Metal5  ;
    ANTENNAMAXSIDEAREACAR 184.513 LAYER Metal5  ;
    ANTENNAMAXCUTCAR 2.54017 LAYER Via5  ;
    PORT
      LAYER Metal5 ;
        RECT 0.000000 21.525000 0.250000 21.605000 ;
    END
  END operand_b_i[1]
  PIN operand_b_i[0]
    DIRECTION INPUT ;
    USE SIGNAL ;
    ANTENNAPARTIALMETALAREA 0.9074 LAYER Metal5  ;
    ANTENNAPARTIALMETALSIDEAREA 4.0518 LAYER Metal5  ;
    ANTENNAMODEL OXIDE1 ;
    ANTENNAGATEAREA 0.02925 LAYER Metal5  ;
    ANTENNAMAXAREACAR 41.8598 LAYER Metal5  ;
    ANTENNAMAXSIDEAREACAR 194.051 LAYER Metal5  ;
    ANTENNAMAXCUTCAR 2.89915 LAYER Via5  ;
    PORT
      LAYER Metal5 ;
        RECT 0.000000 20.575000 0.250000 20.655000 ;
    END
  END operand_b_i[0]
  PIN result_o[63]
    DIRECTION OUTPUT ;
    USE SIGNAL ;
    ANTENNADIFFAREA 3.1578 LAYER Metal6  ;
    ANTENNAPARTIALMETALAREA 0.3424 LAYER Metal6  ;
    ANTENNAPARTIALMETALSIDEAREA 1.5408 LAYER Metal6  ;
    ANTENNAMODEL OXIDE1 ;
    ANTENNAGATEAREA 0.4662 LAYER Metal6  ;
    ANTENNAMAXAREACAR 8.1568 LAYER Metal6  ;
    ANTENNAMAXSIDEAREACAR 55.2072 LAYER Metal6  ;
    ANTENNAMAXCUTCAR 6.27756 LAYER Via6  ;
    PORT
      LAYER Metal6 ;
        RECT 18.260000 0.000000 18.340000 0.250000 ;
    END
  END result_o[63]
  PIN result_o[62]
    DIRECTION OUTPUT ;
    USE SIGNAL ;
    ANTENNADIFFAREA 3.1578 LAYER Metal6  ;
    ANTENNAPARTIALMETALAREA 0.3606 LAYER Metal6  ;
    ANTENNAPARTIALMETALSIDEAREA 1.5912 LAYER Metal6  ;
    ANTENNAMODEL OXIDE1 ;
    ANTENNAGATEAREA 0.4662 LAYER Metal6  ;
    ANTENNAMAXAREACAR 7.57808 LAYER Metal6  ;
    ANTENNAMAXSIDEAREACAR 52.5354 LAYER Metal6  ;
    ANTENNAMAXCUTCAR 6.27756 LAYER Via6  ;
    PORT
      LAYER Metal6 ;
        RECT 19.260000 0.000000 19.340000 0.250000 ;
    END
  END result_o[62]
  PIN result_o[61]
    DIRECTION OUTPUT ;
    USE SIGNAL ;
    ANTENNADIFFAREA 3.1578 LAYER Metal6  ;
    ANTENNAPARTIALMETALAREA 0.7028 LAYER Metal6  ;
    ANTENNAPARTIALMETALSIDEAREA 3.1626 LAYER Metal6  ;
    ANTENNAMODEL OXIDE1 ;
    ANTENNAGATEAREA 0.4662 LAYER Metal6  ;
    ANTENNAMAXAREACAR 8.18855 LAYER Metal6  ;
    ANTENNAMAXSIDEAREACAR 55.3501 LAYER Metal6  ;
    ANTENNAMAXCUTCAR 6.27756 LAYER Via6  ;
    PORT
      LAYER Metal6 ;
        RECT 20.260000 0.000000 20.340000 0.250000 ;
    END
  END result_o[61]
  PIN result_o[60]
    DIRECTION OUTPUT ;
    USE SIGNAL ;
    ANTENNADIFFAREA 3.1578 LAYER Metal6  ;
    ANTENNAPARTIALMETALAREA 0.4184 LAYER Metal6  ;
    ANTENNAPARTIALMETALSIDEAREA 1.8828 LAYER Metal6  ;
    ANTENNAMODEL OXIDE1 ;
    ANTENNAGATEAREA 0.4662 LAYER Metal6  ;
    ANTENNAMAXAREACAR 7.61626 LAYER Metal6  ;
    ANTENNAMAXSIDEAREACAR 52.7748 LAYER Metal6  ;
    ANTENNAMAXCUTCAR 6.27756 LAYER Via6  ;
    PORT
      LAYER Metal6 ;
        RECT 21.260000 0.000000 21.340000 0.250000 ;
    END
  END result_o[60]
  PIN result_o[59]
    DIRECTION OUTPUT ;
    USE SIGNAL ;
    ANTENNADIFFAREA 3.1578 LAYER Metal6  ;
    ANTENNAPARTIALMETALAREA 0.8896 LAYER Metal6  ;
    ANTENNAPARTIALMETALSIDEAREA 4.0032 LAYER Metal6  ;
    ANTENNAMODEL OXIDE1 ;
    ANTENNAGATEAREA 0.4662 LAYER Metal6  ;
    ANTENNAMAXAREACAR 8.60982 LAYER Metal6  ;
    ANTENNAMAXSIDEAREACAR 57.2458 LAYER Metal6  ;
    ANTENNAMAXCUTCAR 6.27756 LAYER Via6  ;
    PORT
      LAYER Metal6 ;
        RECT 22.260000 0.000000 22.340000 0.250000 ;
    END
  END result_o[59]
  PIN result_o[58]
    DIRECTION OUTPUT ;
    USE SIGNAL ;
    ANTENNADIFFAREA 3.1578 LAYER Metal6  ;
    ANTENNAPARTIALMETALAREA 0.6432 LAYER Metal6  ;
    ANTENNAPARTIALMETALSIDEAREA 2.8944 LAYER Metal6  ;
    ANTENNAMODEL OXIDE1 ;
    ANTENNAGATEAREA 0.4662 LAYER Metal6  ;
    ANTENNAMAXAREACAR 7.80202 LAYER Metal6  ;
    ANTENNAMAXSIDEAREACAR 53.6782 LAYER Metal6  ;
    ANTENNAMAXCUTCAR 6.27756 LAYER Via6  ;
    PORT
      LAYER Metal6 ;
        RECT 23.260000 0.000000 23.340000 0.250000 ;
    END
  END result_o[58]
  PIN result_o[57]
    DIRECTION OUTPUT ;
    USE SIGNAL ;
    ANTENNADIFFAREA 3.1578 LAYER Metal6  ;
    ANTENNAPARTIALMETALAREA 0.3424 LAYER Metal6  ;
    ANTENNAPARTIALMETALSIDEAREA 1.5408 LAYER Metal6  ;
    ANTENNAMODEL OXIDE1 ;
    ANTENNAGATEAREA 0.4662 LAYER Metal6  ;
    ANTENNAMAXAREACAR 7.67632 LAYER Metal6  ;
    ANTENNAMAXSIDEAREACAR 53.045 LAYER Metal6  ;
    ANTENNAMAXCUTCAR 6.27756 LAYER Via6  ;
    PORT
      LAYER Metal6 ;
        RECT 24.260000 0.000000 24.340000 0.250000 ;
    END
  END result_o[57]
  PIN result_o[56]
    DIRECTION OUTPUT ;
    USE SIGNAL ;
    ANTENNADIFFAREA 3.1578 LAYER Metal6  ;
    ANTENNAPARTIALMETALAREA 0.7224 LAYER Metal6  ;
    ANTENNAPARTIALMETALSIDEAREA 3.2508 LAYER Metal6  ;
    ANTENNAMODEL OXIDE1 ;
    ANTENNAGATEAREA 0.4662 LAYER Metal6  ;
    ANTENNAMAXAREACAR 8.2958 LAYER Metal6  ;
    ANTENNAMAXSIDEAREACAR 55.8327 LAYER Metal6  ;
    ANTENNAMAXCUTCAR 6.27756 LAYER Via6  ;
    PORT
      LAYER Metal6 ;
        RECT 25.260000 0.000000 25.340000 0.250000 ;
    END
  END result_o[56]
  PIN result_o[55]
    DIRECTION OUTPUT ;
    USE SIGNAL ;
    ANTENNADIFFAREA 3.1578 LAYER Metal6  ;
    ANTENNAPARTIALMETALAREA 1.2696 LAYER Metal6  ;
    ANTENNAPARTIALMETALSIDEAREA 5.7132 LAYER Metal6  ;
    ANTENNAMODEL OXIDE1 ;
    ANTENNAGATEAREA 0.4662 LAYER Metal6  ;
    ANTENNAMAXAREACAR 9.63085 LAYER Metal6  ;
    ANTENNAMAXSIDEAREACAR 61.8404 LAYER Metal6  ;
    ANTENNAMAXCUTCAR 6.27756 LAYER Via6  ;
    PORT
      LAYER Metal6 ;
        RECT 26.260000 0.000000 26.340000 0.250000 ;
    END
  END result_o[55]
  PIN result_o[54]
    DIRECTION OUTPUT ;
    USE SIGNAL ;
    ANTENNADIFFAREA 3.1578 LAYER Metal6  ;
    ANTENNAPARTIALMETALAREA 0.4032 LAYER Metal6  ;
    ANTENNAPARTIALMETALSIDEAREA 1.8144 LAYER Metal6  ;
    ANTENNAMODEL OXIDE1 ;
    ANTENNAGATEAREA 0.4662 LAYER Metal6  ;
    ANTENNAMAXAREACAR 7.95946 LAYER Metal6  ;
    ANTENNAMAXSIDEAREACAR 54.3192 LAYER Metal6  ;
    ANTENNAMAXCUTCAR 6.27756 LAYER Via6  ;
    PORT
      LAYER Metal6 ;
        RECT 27.260000 0.000000 27.340000 0.250000 ;
    END
  END result_o[54]
  PIN result_o[53]
    DIRECTION OUTPUT ;
    USE SIGNAL ;
    ANTENNADIFFAREA 3.1578 LAYER Metal6  ;
    ANTENNAPARTIALMETALAREA 0.3424 LAYER Metal6  ;
    ANTENNAPARTIALMETALSIDEAREA 1.5408 LAYER Metal6  ;
    ANTENNAMODEL OXIDE1 ;
    ANTENNAGATEAREA 0.4662 LAYER Metal6  ;
    ANTENNAMAXAREACAR 7.642 LAYER Metal6  ;
    ANTENNAMAXSIDEAREACAR 52.8906 LAYER Metal6  ;
    ANTENNAMAXCUTCAR 6.27756 LAYER Via6  ;
    PORT
      LAYER Metal6 ;
        RECT 28.260000 0.000000 28.340000 0.250000 ;
    END
  END result_o[53]
  PIN result_o[52]
    DIRECTION OUTPUT ;
    USE SIGNAL ;
    ANTENNADIFFAREA 3.1578 LAYER Metal6  ;
    ANTENNAPARTIALMETALAREA 0.8896 LAYER Metal6  ;
    ANTENNAPARTIALMETALSIDEAREA 4.0032 LAYER Metal6  ;
    ANTENNAMODEL OXIDE1 ;
    ANTENNAGATEAREA 0.4662 LAYER Metal6  ;
    ANTENNAMAXAREACAR 8.78142 LAYER Metal6  ;
    ANTENNAMAXSIDEAREACAR 58.018 LAYER Metal6  ;
    ANTENNAMAXCUTCAR 6.27756 LAYER Via6  ;
    PORT
      LAYER Metal6 ;
        RECT 29.260000 0.000000 29.340000 0.250000 ;
    END
  END result_o[52]
  PIN result_o[51]
    DIRECTION OUTPUT ;
    USE SIGNAL ;
    ANTENNADIFFAREA 3.1578 LAYER Metal6  ;
    ANTENNAPARTIALMETALAREA 0.5552 LAYER Metal6  ;
    ANTENNAPARTIALMETALSIDEAREA 2.4984 LAYER Metal6  ;
    ANTENNAMODEL OXIDE1 ;
    ANTENNAGATEAREA 0.4662 LAYER Metal6  ;
    ANTENNAMAXAREACAR 8.47941 LAYER Metal6  ;
    ANTENNAMAXSIDEAREACAR 56.6589 LAYER Metal6  ;
    ANTENNAMAXCUTCAR 6.27756 LAYER Via6  ;
    PORT
      LAYER Metal6 ;
        RECT 30.260000 0.000000 30.340000 0.250000 ;
    END
  END result_o[51]
  PIN result_o[50]
    DIRECTION OUTPUT ;
    USE SIGNAL ;
    ANTENNADIFFAREA 3.1578 LAYER Metal6  ;
    ANTENNAPARTIALMETALAREA 0.4184 LAYER Metal6  ;
    ANTENNAPARTIALMETALSIDEAREA 1.8828 LAYER Metal6  ;
    ANTENNAMODEL OXIDE1 ;
    ANTENNAGATEAREA 0.4662 LAYER Metal6  ;
    ANTENNAMAXAREACAR 7.91484 LAYER Metal6  ;
    ANTENNAMAXSIDEAREACAR 54.1184 LAYER Metal6  ;
    ANTENNAMAXCUTCAR 6.27756 LAYER Via6  ;
    PORT
      LAYER Metal6 ;
        RECT 31.260000 0.000000 31.340000 0.250000 ;
    END
  END result_o[50]
  PIN result_o[49]
    DIRECTION OUTPUT ;
    USE SIGNAL ;
    ANTENNADIFFAREA 3.1578 LAYER Metal6  ;
    ANTENNAPARTIALMETALAREA 0.8364 LAYER Metal6  ;
    ANTENNAPARTIALMETALSIDEAREA 3.7638 LAYER Metal6  ;
    ANTENNAMODEL OXIDE1 ;
    ANTENNAGATEAREA 0.4662 LAYER Metal6  ;
    ANTENNAMAXAREACAR 8.36873 LAYER Metal6  ;
    ANTENNAMAXSIDEAREACAR 56.1609 LAYER Metal6  ;
    ANTENNAMAXCUTCAR 6.27756 LAYER Via6  ;
    PORT
      LAYER Metal6 ;
        RECT 32.260000 0.000000 32.340000 0.250000 ;
    END
  END result_o[49]
  PIN result_o[48]
    DIRECTION OUTPUT ;
    USE SIGNAL ;
    ANTENNADIFFAREA 3.12228 LAYER Metal6  ;
    ANTENNAPARTIALMETALAREA 0.1782 LAYER Metal6  ;
    ANTENNAPARTIALMETALSIDEAREA 0.7704 LAYER Metal6  ;
    PORT
      LAYER Metal6 ;
        RECT 33.260000 0.000000 33.340000 0.250000 ;
    END
  END result_o[48]
  PIN result_o[47]
    DIRECTION OUTPUT ;
    USE SIGNAL ;
    ANTENNADIFFAREA 3.1578 LAYER Metal6  ;
    ANTENNAPARTIALMETALAREA 0.6494 LAYER Metal6  ;
    ANTENNAPARTIALMETALSIDEAREA 2.8908 LAYER Metal6  ;
    ANTENNAMODEL OXIDE1 ;
    ANTENNAGATEAREA 0.4662 LAYER Metal6  ;
    ANTENNAMAXAREACAR 11.3897 LAYER Metal6  ;
    ANTENNAMAXSIDEAREACAR 69.7555 LAYER Metal6  ;
    ANTENNAMAXCUTCAR 6.27756 LAYER Via6  ;
    PORT
      LAYER Metal6 ;
        RECT 34.260000 0.000000 34.340000 0.250000 ;
    END
  END result_o[47]
  PIN result_o[46]
    DIRECTION OUTPUT ;
    USE SIGNAL ;
    ANTENNADIFFAREA 3.839 LAYER Metal6  ;
    ANTENNAPARTIALMETALAREA 0.467 LAYER Metal6  ;
    ANTENNAPARTIALMETALSIDEAREA 2.07 LAYER Metal6  ;
    ANTENNAMODEL OXIDE1 ;
    ANTENNAGATEAREA 0.585 LAYER Metal6  ;
    ANTENNAMAXAREACAR 10.9285 LAYER Metal6  ;
    ANTENNAMAXSIDEAREACAR 68.022 LAYER Metal6  ;
    ANTENNAMAXCUTCAR 6.47111 LAYER Via6  ;
    PORT
      LAYER Metal6 ;
        RECT 35.260000 0.000000 35.340000 0.250000 ;
    END
  END result_o[46]
  PIN result_o[45]
    DIRECTION OUTPUT ;
    USE SIGNAL ;
    ANTENNADIFFAREA 3.839 LAYER Metal6  ;
    ANTENNAPARTIALMETALAREA 0.6708 LAYER Metal6  ;
    ANTENNAPARTIALMETALSIDEAREA 3.0186 LAYER Metal6  ;
    ANTENNAMODEL OXIDE1 ;
    ANTENNAGATEAREA 0.585 LAYER Metal6  ;
    ANTENNAMAXAREACAR 8.66872 LAYER Metal6  ;
    ANTENNAMAXSIDEAREACAR 57.8528 LAYER Metal6  ;
    ANTENNAMAXCUTCAR 6.47111 LAYER Via6  ;
    PORT
      LAYER Metal6 ;
        RECT 36.260000 0.000000 36.340000 0.250000 ;
    END
  END result_o[45]
  PIN result_o[44]
    DIRECTION OUTPUT ;
    USE SIGNAL ;
    ANTENNADIFFAREA 3.839 LAYER Metal6  ;
    ANTENNAPARTIALMETALAREA 0.4974 LAYER Metal6  ;
    ANTENNAPARTIALMETALSIDEAREA 2.2068 LAYER Metal6  ;
    ANTENNAMODEL OXIDE1 ;
    ANTENNAGATEAREA 0.585 LAYER Metal6  ;
    ANTENNAMAXAREACAR 8.78838 LAYER Metal6  ;
    ANTENNAMAXSIDEAREACAR 58.3913 LAYER Metal6  ;
    ANTENNAMAXCUTCAR 6.47111 LAYER Via6  ;
    PORT
      LAYER Metal6 ;
        RECT 37.260000 0.000000 37.340000 0.250000 ;
    END
  END result_o[44]
  PIN result_o[43]
    DIRECTION OUTPUT ;
    USE SIGNAL ;
    ANTENNADIFFAREA 3.1578 LAYER Metal6  ;
    ANTENNAPARTIALMETALAREA 0.7254 LAYER Metal6  ;
    ANTENNAPARTIALMETALSIDEAREA 3.2328 LAYER Metal6  ;
    ANTENNAMODEL OXIDE1 ;
    ANTENNAGATEAREA 0.4662 LAYER Metal6  ;
    ANTENNAMAXAREACAR 9.80245 LAYER Metal6  ;
    ANTENNAMAXSIDEAREACAR 62.6126 LAYER Metal6  ;
    ANTENNAMAXCUTCAR 6.27756 LAYER Via6  ;
    PORT
      LAYER Metal6 ;
        RECT 38.260000 0.000000 38.340000 0.250000 ;
    END
  END result_o[43]
  PIN result_o[42]
    DIRECTION OUTPUT ;
    USE SIGNAL ;
    ANTENNADIFFAREA 3.1578 LAYER Metal6  ;
    ANTENNAPARTIALMETALAREA 0.3424 LAYER Metal6  ;
    ANTENNAPARTIALMETALSIDEAREA 1.5408 LAYER Metal6  ;
    ANTENNAMODEL OXIDE1 ;
    ANTENNAGATEAREA 0.4662 LAYER Metal6  ;
    ANTENNAMAXAREACAR 7.77928 LAYER Metal6  ;
    ANTENNAMAXSIDEAREACAR 53.5084 LAYER Metal6  ;
    ANTENNAMAXCUTCAR 6.27756 LAYER Via6  ;
    PORT
      LAYER Metal6 ;
        RECT 39.260000 0.000000 39.340000 0.250000 ;
    END
  END result_o[42]
  PIN result_o[41]
    DIRECTION OUTPUT ;
    USE SIGNAL ;
    ANTENNADIFFAREA 3.1578 LAYER Metal6  ;
    ANTENNAPARTIALMETALAREA 0.4488 LAYER Metal6  ;
    ANTENNAPARTIALMETALSIDEAREA 2.0196 LAYER Metal6  ;
    ANTENNAMODEL OXIDE1 ;
    ANTENNAGATEAREA 0.4662 LAYER Metal6  ;
    ANTENNAMAXAREACAR 7.76727 LAYER Metal6  ;
    ANTENNAMAXSIDEAREACAR 53.4543 LAYER Metal6  ;
    ANTENNAMAXCUTCAR 6.27756 LAYER Via6  ;
    PORT
      LAYER Metal6 ;
        RECT 40.260000 0.000000 40.340000 0.250000 ;
    END
  END result_o[41]
  PIN result_o[40]
    DIRECTION OUTPUT ;
    USE SIGNAL ;
    ANTENNADIFFAREA 3.1578 LAYER Metal6  ;
    ANTENNAPARTIALMETALAREA 0.616 LAYER Metal6  ;
    ANTENNAPARTIALMETALSIDEAREA 2.772 LAYER Metal6  ;
    ANTENNAMODEL OXIDE1 ;
    ANTENNAGATEAREA 0.4662 LAYER Metal6  ;
    ANTENNAMAXAREACAR 8.19455 LAYER Metal6  ;
    ANTENNAMAXSIDEAREACAR 55.3771 LAYER Metal6  ;
    ANTENNAMAXCUTCAR 6.27756 LAYER Via6  ;
    PORT
      LAYER Metal6 ;
        RECT 41.260000 0.000000 41.340000 0.250000 ;
    END
  END result_o[40]
  PIN result_o[39]
    DIRECTION OUTPUT ;
    USE SIGNAL ;
    ANTENNADIFFAREA 3.1578 LAYER Metal6  ;
    ANTENNAPARTIALMETALAREA 0.46 LAYER Metal6  ;
    ANTENNAPARTIALMETALSIDEAREA 2.07 LAYER Metal6  ;
    ANTENNAMODEL OXIDE1 ;
    ANTENNAGATEAREA 0.4662 LAYER Metal6  ;
    ANTENNAMAXAREACAR 7.49271 LAYER Metal6  ;
    ANTENNAMAXSIDEAREACAR 52.2188 LAYER Metal6  ;
    ANTENNAMAXCUTCAR 6.27756 LAYER Via6  ;
    PORT
      LAYER Metal6 ;
        RECT 42.260000 0.000000 42.340000 0.250000 ;
    END
  END result_o[39]
  PIN result_o[38]
    DIRECTION OUTPUT ;
    USE SIGNAL ;
    ANTENNADIFFAREA 3.1578 LAYER Metal6  ;
    ANTENNAPARTIALMETALAREA 0.3424 LAYER Metal6  ;
    ANTENNAPARTIALMETALSIDEAREA 1.5408 LAYER Metal6  ;
    ANTENNAMODEL OXIDE1 ;
    ANTENNAGATEAREA 0.4662 LAYER Metal6  ;
    ANTENNAMAXAREACAR 7.67632 LAYER Metal6  ;
    ANTENNAMAXSIDEAREACAR 53.045 LAYER Metal6  ;
    ANTENNAMAXCUTCAR 6.27756 LAYER Via6  ;
    PORT
      LAYER Metal6 ;
        RECT 43.260000 0.000000 43.340000 0.250000 ;
    END
  END result_o[38]
  PIN result_o[37]
    DIRECTION OUTPUT ;
    USE SIGNAL ;
    ANTENNADIFFAREA 3.1578 LAYER Metal6  ;
    ANTENNAPARTIALMETALAREA 0.6272 LAYER Metal6  ;
    ANTENNAPARTIALMETALSIDEAREA 2.8224 LAYER Metal6  ;
    ANTENNAMODEL OXIDE1 ;
    ANTENNAGATEAREA 0.4662 LAYER Metal6  ;
    ANTENNAMAXAREACAR 7.95431 LAYER Metal6  ;
    ANTENNAMAXSIDEAREACAR 54.296 LAYER Metal6  ;
    ANTENNAMAXCUTCAR 6.27756 LAYER Via6  ;
    PORT
      LAYER Metal6 ;
        RECT 44.260000 0.000000 44.340000 0.250000 ;
    END
  END result_o[37]
  PIN result_o[36]
    DIRECTION OUTPUT ;
    USE SIGNAL ;
    ANTENNADIFFAREA 3.1578 LAYER Metal6  ;
    ANTENNAPARTIALMETALAREA 0.3536 LAYER Metal6  ;
    ANTENNAPARTIALMETALSIDEAREA 1.5912 LAYER Metal6  ;
    ANTENNAMODEL OXIDE1 ;
    ANTENNAGATEAREA 0.4662 LAYER Metal6  ;
    ANTENNAMAXAREACAR 7.2988 LAYER Metal6  ;
    ANTENNAMAXSIDEAREACAR 51.3462 LAYER Metal6  ;
    ANTENNAMAXCUTCAR 6.27756 LAYER Via6  ;
    PORT
      LAYER Metal6 ;
        RECT 45.260000 0.000000 45.340000 0.250000 ;
    END
  END result_o[36]
  PIN result_o[35]
    DIRECTION OUTPUT ;
    USE SIGNAL ;
    ANTENNADIFFAREA 3.1578 LAYER Metal6  ;
    ANTENNAPARTIALMETALAREA 0.6272 LAYER Metal6  ;
    ANTENNAPARTIALMETALSIDEAREA 2.8224 LAYER Metal6  ;
    ANTENNAMODEL OXIDE1 ;
    ANTENNAGATEAREA 0.4662 LAYER Metal6  ;
    ANTENNAMAXAREACAR 8.36615 LAYER Metal6  ;
    ANTENNAMAXSIDEAREACAR 56.1493 LAYER Metal6  ;
    ANTENNAMAXCUTCAR 6.27756 LAYER Via6  ;
    PORT
      LAYER Metal6 ;
        RECT 46.260000 0.000000 46.340000 0.250000 ;
    END
  END result_o[35]
  PIN result_o[34]
    DIRECTION OUTPUT ;
    USE SIGNAL ;
    ANTENNADIFFAREA 3.1578 LAYER Metal6  ;
    ANTENNAPARTIALMETALAREA 0.9328 LAYER Metal6  ;
    ANTENNAPARTIALMETALSIDEAREA 4.1976 LAYER Metal6  ;
    ANTENNAMODEL OXIDE1 ;
    ANTENNAGATEAREA 0.4662 LAYER Metal6  ;
    ANTENNAMAXAREACAR 8.7471 LAYER Metal6  ;
    ANTENNAMAXSIDEAREACAR 57.8636 LAYER Metal6  ;
    ANTENNAMAXCUTCAR 6.27756 LAYER Via6  ;
    PORT
      LAYER Metal6 ;
        RECT 47.260000 0.000000 47.340000 0.250000 ;
    END
  END result_o[34]
  PIN result_o[33]
    DIRECTION OUTPUT ;
    USE SIGNAL ;
    ANTENNADIFFAREA 3.1578 LAYER Metal6  ;
    ANTENNAPARTIALMETALAREA 0.8044 LAYER Metal6  ;
    ANTENNAPARTIALMETALSIDEAREA 3.6198 LAYER Metal6  ;
    ANTENNAMODEL OXIDE1 ;
    ANTENNAGATEAREA 0.4662 LAYER Metal6  ;
    ANTENNAMAXAREACAR 8.19713 LAYER Metal6  ;
    ANTENNAMAXSIDEAREACAR 55.3887 LAYER Metal6  ;
    ANTENNAMAXCUTCAR 6.27756 LAYER Via6  ;
    PORT
      LAYER Metal6 ;
        RECT 48.260000 0.000000 48.340000 0.250000 ;
    END
  END result_o[33]
  PIN result_o[32]
    DIRECTION OUTPUT ;
    USE SIGNAL ;
    ANTENNADIFFAREA 3.1578 LAYER Metal6  ;
    ANTENNAPARTIALMETALAREA 0.4488 LAYER Metal6  ;
    ANTENNAPARTIALMETALSIDEAREA 2.0196 LAYER Metal6  ;
    ANTENNAMODEL OXIDE1 ;
    ANTENNAGATEAREA 0.4662 LAYER Metal6  ;
    ANTENNAMAXAREACAR 7.83591 LAYER Metal6  ;
    ANTENNAMAXSIDEAREACAR 53.7632 LAYER Metal6  ;
    ANTENNAMAXCUTCAR 6.27756 LAYER Via6  ;
    PORT
      LAYER Metal6 ;
        RECT 49.260000 0.000000 49.340000 0.250000 ;
    END
  END result_o[32]
  PIN result_o[31]
    DIRECTION OUTPUT ;
    USE SIGNAL ;
    ANTENNADIFFAREA 3.1578 LAYER Metal6  ;
    ANTENNAPARTIALMETALAREA 0.3536 LAYER Metal6  ;
    ANTENNAPARTIALMETALSIDEAREA 1.5912 LAYER Metal6  ;
    ANTENNAMODEL OXIDE1 ;
    ANTENNAGATEAREA 0.4662 LAYER Metal6  ;
    ANTENNAMAXAREACAR 7.33312 LAYER Metal6  ;
    ANTENNAMAXSIDEAREACAR 51.5006 LAYER Metal6  ;
    ANTENNAMAXCUTCAR 6.27756 LAYER Via6  ;
    PORT
      LAYER Metal6 ;
        RECT 50.260000 0.000000 50.340000 0.250000 ;
    END
  END result_o[31]
  PIN result_o[30]
    DIRECTION OUTPUT ;
    USE SIGNAL ;
    ANTENNADIFFAREA 3.839 LAYER Metal6  ;
    ANTENNAPARTIALMETALAREA 2.7856 LAYER Metal6  ;
    ANTENNAPARTIALMETALSIDEAREA 12.5352 LAYER Metal6  ;
    ANTENNAMODEL OXIDE1 ;
    ANTENNAGATEAREA 0.585 LAYER Metal6  ;
    ANTENNAMAXAREACAR 11.9597 LAYER Metal6  ;
    ANTENNAMAXSIDEAREACAR 72.662 LAYER Metal6  ;
    ANTENNAMAXCUTCAR 6.47111 LAYER Via6  ;
    PORT
      LAYER Metal6 ;
        RECT 51.260000 0.000000 51.340000 0.250000 ;
    END
  END result_o[30]
  PIN result_o[29]
    DIRECTION OUTPUT ;
    USE SIGNAL ;
    ANTENNADIFFAREA 3.1578 LAYER Metal6  ;
    ANTENNAPARTIALMETALAREA 0.5148 LAYER Metal6  ;
    ANTENNAPARTIALMETALSIDEAREA 2.3166 LAYER Metal6  ;
    ANTENNAMODEL OXIDE1 ;
    ANTENNAGATEAREA 0.4662 LAYER Metal6  ;
    ANTENNAMAXAREACAR 7.71321 LAYER Metal6  ;
    ANTENNAMAXSIDEAREACAR 53.2111 LAYER Metal6  ;
    ANTENNAMAXCUTCAR 6.27756 LAYER Via6  ;
    PORT
      LAYER Metal6 ;
        RECT 52.260000 0.000000 52.340000 0.250000 ;
    END
  END result_o[29]
  PIN result_o[28]
    DIRECTION OUTPUT ;
    USE SIGNAL ;
    ANTENNADIFFAREA 3.1578 LAYER Metal6  ;
    ANTENNAPARTIALMETALAREA 0.9008 LAYER Metal6  ;
    ANTENNAPARTIALMETALSIDEAREA 4.0536 LAYER Metal6  ;
    ANTENNAMODEL OXIDE1 ;
    ANTENNAGATEAREA 0.4662 LAYER Metal6  ;
    ANTENNAMAXAREACAR 8.33054 LAYER Metal6  ;
    ANTENNAMAXSIDEAREACAR 56.0566 LAYER Metal6  ;
    ANTENNAMAXCUTCAR 6.27756 LAYER Via6  ;
    PORT
      LAYER Metal6 ;
        RECT 53.260000 0.000000 53.340000 0.250000 ;
    END
  END result_o[28]
  PIN result_o[27]
    DIRECTION OUTPUT ;
    USE SIGNAL ;
    ANTENNADIFFAREA 3.1578 LAYER Metal6  ;
    ANTENNAPARTIALMETALAREA 0.6432 LAYER Metal6  ;
    ANTENNAPARTIALMETALSIDEAREA 2.8944 LAYER Metal6  ;
    ANTENNAMODEL OXIDE1 ;
    ANTENNAGATEAREA 0.4662 LAYER Metal6  ;
    ANTENNAMAXAREACAR 7.77799 LAYER Metal6  ;
    ANTENNAMAXSIDEAREACAR 53.5701 LAYER Metal6  ;
    ANTENNAMAXCUTCAR 6.27756 LAYER Via6  ;
    PORT
      LAYER Metal6 ;
        RECT 54.260000 0.000000 54.340000 0.250000 ;
    END
  END result_o[27]
  PIN result_o[26]
    DIRECTION OUTPUT ;
    USE SIGNAL ;
    ANTENNADIFFAREA 3.1578 LAYER Metal6  ;
    ANTENNAPARTIALMETALAREA 0.3536 LAYER Metal6  ;
    ANTENNAPARTIALMETALSIDEAREA 1.5912 LAYER Metal6  ;
    ANTENNAMODEL OXIDE1 ;
    ANTENNAGATEAREA 0.4662 LAYER Metal6  ;
    ANTENNAMAXAREACAR 7.40176 LAYER Metal6  ;
    ANTENNAMAXSIDEAREACAR 51.8095 LAYER Metal6  ;
    ANTENNAMAXCUTCAR 6.27756 LAYER Via6  ;
    PORT
      LAYER Metal6 ;
        RECT 55.260000 0.000000 55.340000 0.250000 ;
    END
  END result_o[26]
  PIN result_o[25]
    DIRECTION OUTPUT ;
    USE SIGNAL ;
    ANTENNADIFFAREA 3.1578 LAYER Metal6  ;
    ANTENNAPARTIALMETALAREA 0.7336 LAYER Metal6  ;
    ANTENNAPARTIALMETALSIDEAREA 3.3012 LAYER Metal6  ;
    ANTENNAMODEL OXIDE1 ;
    ANTENNAGATEAREA 0.4662 LAYER Metal6  ;
    ANTENNAMAXAREACAR 8.18254 LAYER Metal6  ;
    ANTENNAMAXSIDEAREACAR 55.323 LAYER Metal6  ;
    ANTENNAMAXCUTCAR 6.27756 LAYER Via6  ;
    PORT
      LAYER Metal6 ;
        RECT 56.260000 0.000000 56.340000 0.250000 ;
    END
  END result_o[25]
  PIN result_o[24]
    DIRECTION OUTPUT ;
    USE SIGNAL ;
    ANTENNADIFFAREA 3.839 LAYER Metal6  ;
    ANTENNAPARTIALMETALAREA 0.4822 LAYER Metal6  ;
    ANTENNAPARTIALMETALSIDEAREA 2.1384 LAYER Metal6  ;
    ANTENNAMODEL OXIDE1 ;
    ANTENNAGATEAREA 0.585 LAYER Metal6  ;
    ANTENNAMAXAREACAR 9.68137 LAYER Metal6  ;
    ANTENNAMAXSIDEAREACAR 62.4097 LAYER Metal6  ;
    ANTENNAMAXCUTCAR 6.47111 LAYER Via6  ;
    PORT
      LAYER Metal6 ;
        RECT 57.260000 0.000000 57.340000 0.250000 ;
    END
  END result_o[24]
  PIN result_o[23]
    DIRECTION OUTPUT ;
    USE SIGNAL ;
    ANTENNADIFFAREA 3.1578 LAYER Metal6  ;
    ANTENNAPARTIALMETALAREA 0.8288 LAYER Metal6  ;
    ANTENNAPARTIALMETALSIDEAREA 3.7296 LAYER Metal6  ;
    ANTENNAMODEL OXIDE1 ;
    ANTENNAGATEAREA 0.4662 LAYER Metal6  ;
    ANTENNAMAXAREACAR 9.75268 LAYER Metal6  ;
    ANTENNAMAXSIDEAREACAR 62.3887 LAYER Metal6  ;
    ANTENNAMAXCUTCAR 6.27756 LAYER Via6  ;
    PORT
      LAYER Metal6 ;
        RECT 58.260000 0.000000 58.340000 0.250000 ;
    END
  END result_o[23]
  PIN result_o[22]
    DIRECTION OUTPUT ;
    USE SIGNAL ;
    ANTENNADIFFAREA 3.1578 LAYER Metal6  ;
    ANTENNAPARTIALMETALAREA 0.3536 LAYER Metal6  ;
    ANTENNAPARTIALMETALSIDEAREA 1.5912 LAYER Metal6  ;
    ANTENNAMODEL OXIDE1 ;
    ANTENNAGATEAREA 0.4662 LAYER Metal6  ;
    ANTENNAMAXAREACAR 7.33312 LAYER Metal6  ;
    ANTENNAMAXSIDEAREACAR 51.5006 LAYER Metal6  ;
    ANTENNAMAXCUTCAR 6.27756 LAYER Via6  ;
    PORT
      LAYER Metal6 ;
        RECT 59.260000 0.000000 59.340000 0.250000 ;
    END
  END result_o[22]
  PIN result_o[21]
    DIRECTION OUTPUT ;
    USE SIGNAL ;
    ANTENNADIFFAREA 3.1578 LAYER Metal6  ;
    ANTENNAPARTIALMETALAREA 1.0142 LAYER Metal6  ;
    ANTENNAPARTIALMETALSIDEAREA 4.5324 LAYER Metal6  ;
    ANTENNAMODEL OXIDE1 ;
    ANTENNAGATEAREA 0.4662 LAYER Metal6  ;
    ANTENNAMAXAREACAR 9.11733 LAYER Metal6  ;
    ANTENNAMAXSIDEAREACAR 59.462 LAYER Metal6  ;
    ANTENNAMAXCUTCAR 6.27756 LAYER Via6  ;
    PORT
      LAYER Metal6 ;
        RECT 60.260000 0.000000 60.340000 0.250000 ;
    END
  END result_o[21]
  PIN result_o[20]
    DIRECTION OUTPUT ;
    USE SIGNAL ;
    ANTENNADIFFAREA 3.1578 LAYER Metal6  ;
    ANTENNAPARTIALMETALAREA 0.8896 LAYER Metal6  ;
    ANTENNAPARTIALMETALSIDEAREA 4.0032 LAYER Metal6  ;
    ANTENNAMODEL OXIDE1 ;
    ANTENNAGATEAREA 0.4662 LAYER Metal6  ;
    ANTENNAMAXAREACAR 8.81574 LAYER Metal6  ;
    ANTENNAMAXSIDEAREACAR 58.1725 LAYER Metal6  ;
    ANTENNAMAXCUTCAR 6.27756 LAYER Via6  ;
    PORT
      LAYER Metal6 ;
        RECT 61.260000 0.000000 61.340000 0.250000 ;
    END
  END result_o[20]
  PIN result_o[19]
    DIRECTION OUTPUT ;
    USE SIGNAL ;
    ANTENNADIFFAREA 3.1578 LAYER Metal6  ;
    ANTENNAPARTIALMETALAREA 0.4488 LAYER Metal6  ;
    ANTENNAPARTIALMETALSIDEAREA 2.0196 LAYER Metal6  ;
    ANTENNAMODEL OXIDE1 ;
    ANTENNAGATEAREA 0.4662 LAYER Metal6  ;
    ANTENNAMAXAREACAR 8.59095 LAYER Metal6  ;
    ANTENNAMAXSIDEAREACAR 57.1609 LAYER Metal6  ;
    ANTENNAMAXCUTCAR 6.27756 LAYER Via6  ;
    PORT
      LAYER Metal6 ;
        RECT 62.260000 0.000000 62.340000 0.250000 ;
    END
  END result_o[19]
  PIN result_o[18]
    DIRECTION OUTPUT ;
    USE SIGNAL ;
    ANTENNADIFFAREA 3.1578 LAYER Metal6  ;
    ANTENNAPARTIALMETALAREA 0.1782 LAYER Metal6  ;
    ANTENNAPARTIALMETALSIDEAREA 0.7704 LAYER Metal6  ;
    ANTENNAMODEL OXIDE1 ;
    ANTENNAGATEAREA 0.4662 LAYER Metal6  ;
    ANTENNAMAXAREACAR 8.15294 LAYER Metal6  ;
    ANTENNAMAXSIDEAREACAR 55.1223 LAYER Metal6  ;
    ANTENNAMAXCUTCAR 6.27756 LAYER Via6  ;
    PORT
      LAYER Metal6 ;
        RECT 63.260000 0.000000 63.340000 0.250000 ;
    END
  END result_o[18]
  PIN result_o[17]
    DIRECTION OUTPUT ;
    USE SIGNAL ;
    ANTENNADIFFAREA 3.1578 LAYER Metal6  ;
    ANTENNAPARTIALMETALAREA 0.7508 LAYER Metal6  ;
    ANTENNAPARTIALMETALSIDEAREA 3.3786 LAYER Metal6  ;
    ANTENNAMODEL OXIDE1 ;
    ANTENNAGATEAREA 0.4662 LAYER Metal6  ;
    ANTENNAMAXAREACAR 8.75826 LAYER Metal6  ;
    ANTENNAMAXSIDEAREACAR 57.9138 LAYER Metal6  ;
    ANTENNAMAXCUTCAR 6.27756 LAYER Via6  ;
    PORT
      LAYER Metal6 ;
        RECT 64.260000 0.000000 64.340000 0.250000 ;
    END
  END result_o[17]
  PIN result_o[16]
    DIRECTION OUTPUT ;
    USE SIGNAL ;
    ANTENNADIFFAREA 3.1578 LAYER Metal6  ;
    ANTENNAPARTIALMETALAREA 0.7224 LAYER Metal6  ;
    ANTENNAPARTIALMETALSIDEAREA 3.2508 LAYER Metal6  ;
    ANTENNAMODEL OXIDE1 ;
    ANTENNAGATEAREA 0.4662 LAYER Metal6  ;
    ANTENNAMAXAREACAR 8.8003 LAYER Metal6  ;
    ANTENNAMAXSIDEAREACAR 58.103 LAYER Metal6  ;
    ANTENNAMAXCUTCAR 6.27756 LAYER Via6  ;
    PORT
      LAYER Metal6 ;
        RECT 65.260000 0.000000 65.340000 0.250000 ;
    END
  END result_o[16]
  PIN result_o[15]
    DIRECTION OUTPUT ;
    USE SIGNAL ;
    ANTENNADIFFAREA 3.1578 LAYER Metal6  ;
    ANTENNAPARTIALMETALAREA 0.3424 LAYER Metal6  ;
    ANTENNAPARTIALMETALSIDEAREA 1.5408 LAYER Metal6  ;
    ANTENNAMODEL OXIDE1 ;
    ANTENNAGATEAREA 0.4662 LAYER Metal6  ;
    ANTENNAMAXAREACAR 7.77928 LAYER Metal6  ;
    ANTENNAMAXSIDEAREACAR 53.5084 LAYER Metal6  ;
    ANTENNAMAXCUTCAR 6.27756 LAYER Via6  ;
    PORT
      LAYER Metal6 ;
        RECT 66.260000 0.000000 66.340000 0.250000 ;
    END
  END result_o[15]
  PIN result_o[14]
    DIRECTION OUTPUT ;
    USE SIGNAL ;
    ANTENNADIFFAREA 3.1578 LAYER Metal6  ;
    ANTENNAPARTIALMETALAREA 0.616 LAYER Metal6  ;
    ANTENNAPARTIALMETALSIDEAREA 2.772 LAYER Metal6  ;
    ANTENNAMODEL OXIDE1 ;
    ANTENNAGATEAREA 0.4662 LAYER Metal6  ;
    ANTENNAMAXAREACAR 8.22887 LAYER Metal6  ;
    ANTENNAMAXSIDEAREACAR 55.5315 LAYER Metal6  ;
    ANTENNAMAXCUTCAR 6.27756 LAYER Via6  ;
    PORT
      LAYER Metal6 ;
        RECT 67.260000 0.000000 67.340000 0.250000 ;
    END
  END result_o[14]
  PIN result_o[13]
    DIRECTION OUTPUT ;
    USE SIGNAL ;
    ANTENNADIFFAREA 3.1578 LAYER Metal6  ;
    ANTENNAPARTIALMETALAREA 0.4084 LAYER Metal6  ;
    ANTENNAPARTIALMETALSIDEAREA 1.8378 LAYER Metal6  ;
    ANTENNAMODEL OXIDE1 ;
    ANTENNAGATEAREA 0.4662 LAYER Metal6  ;
    ANTENNAMAXAREACAR 7.48498 LAYER Metal6  ;
    ANTENNAMAXSIDEAREACAR 52.184 LAYER Metal6  ;
    ANTENNAMAXCUTCAR 6.27756 LAYER Via6  ;
    PORT
      LAYER Metal6 ;
        RECT 68.260000 0.000000 68.340000 0.250000 ;
    END
  END result_o[13]
  PIN result_o[12]
    DIRECTION OUTPUT ;
    USE SIGNAL ;
    ANTENNADIFFAREA 3.1578 LAYER Metal6  ;
    ANTENNAPARTIALMETALAREA 0.46 LAYER Metal6  ;
    ANTENNAPARTIALMETALSIDEAREA 2.07 LAYER Metal6  ;
    ANTENNAMODEL OXIDE1 ;
    ANTENNAGATEAREA 0.4662 LAYER Metal6  ;
    ANTENNAMAXAREACAR 7.61969 LAYER Metal6  ;
    ANTENNAMAXSIDEAREACAR 52.7902 LAYER Metal6  ;
    ANTENNAMAXCUTCAR 6.27756 LAYER Via6  ;
    PORT
      LAYER Metal6 ;
        RECT 69.260000 0.000000 69.340000 0.250000 ;
    END
  END result_o[12]
  PIN result_o[11]
    DIRECTION OUTPUT ;
    USE SIGNAL ;
    ANTENNADIFFAREA 3.1578 LAYER Metal6  ;
    ANTENNAPARTIALMETALAREA 0.3536 LAYER Metal6  ;
    ANTENNAPARTIALMETALSIDEAREA 1.5912 LAYER Metal6  ;
    ANTENNAMODEL OXIDE1 ;
    ANTENNAGATEAREA 0.4662 LAYER Metal6  ;
    ANTENNAMAXAREACAR 7.43608 LAYER Metal6  ;
    ANTENNAMAXSIDEAREACAR 51.964 LAYER Metal6  ;
    ANTENNAMAXCUTCAR 6.27756 LAYER Via6  ;
    PORT
      LAYER Metal6 ;
        RECT 70.260000 0.000000 70.340000 0.250000 ;
    END
  END result_o[11]
  PIN result_o[10]
    DIRECTION OUTPUT ;
    USE SIGNAL ;
    ANTENNADIFFAREA 3.1578 LAYER Metal6  ;
    ANTENNAPARTIALMETALAREA 0.1782 LAYER Metal6  ;
    ANTENNAPARTIALMETALSIDEAREA 0.7704 LAYER Metal6  ;
    ANTENNAMODEL OXIDE1 ;
    ANTENNAGATEAREA 0.4662 LAYER Metal6  ;
    ANTENNAMAXAREACAR 8.13621 LAYER Metal6  ;
    ANTENNAMAXSIDEAREACAR 55.1145 LAYER Metal6  ;
    ANTENNAMAXCUTCAR 6.27756 LAYER Via6  ;
    PORT
      LAYER Metal6 ;
        RECT 71.260000 0.000000 71.340000 0.250000 ;
    END
  END result_o[10]
  PIN result_o[9]
    DIRECTION OUTPUT ;
    USE SIGNAL ;
    ANTENNADIFFAREA 3.1578 LAYER Metal6  ;
    ANTENNAPARTIALMETALAREA 0.4032 LAYER Metal6  ;
    ANTENNAPARTIALMETALSIDEAREA 1.8144 LAYER Metal6  ;
    ANTENNAMODEL OXIDE1 ;
    ANTENNAGATEAREA 0.4662 LAYER Metal6  ;
    ANTENNAMAXAREACAR 8.49828 LAYER Metal6  ;
    ANTENNAMAXSIDEAREACAR 56.7439 LAYER Metal6  ;
    ANTENNAMAXCUTCAR 6.27756 LAYER Via6  ;
    PORT
      LAYER Metal6 ;
        RECT 72.260000 0.000000 72.340000 0.250000 ;
    END
  END result_o[9]
  PIN result_o[8]
    DIRECTION OUTPUT ;
    USE SIGNAL ;
    ANTENNADIFFAREA 3.1578 LAYER Metal6  ;
    ANTENNAPARTIALMETALAREA 0.3536 LAYER Metal6  ;
    ANTENNAPARTIALMETALSIDEAREA 1.5912 LAYER Metal6  ;
    ANTENNAMODEL OXIDE1 ;
    ANTENNAGATEAREA 0.4662 LAYER Metal6  ;
    ANTENNAMAXAREACAR 8.43136 LAYER Metal6  ;
    ANTENNAMAXSIDEAREACAR 56.4427 LAYER Metal6  ;
    ANTENNAMAXCUTCAR 6.27756 LAYER Via6  ;
    PORT
      LAYER Metal6 ;
        RECT 73.260000 0.000000 73.340000 0.250000 ;
    END
  END result_o[8]
  PIN result_o[7]
    DIRECTION OUTPUT ;
    USE SIGNAL ;
    ANTENNADIFFAREA 3.1578 LAYER Metal6  ;
    ANTENNAPARTIALMETALAREA 0.46 LAYER Metal6  ;
    ANTENNAPARTIALMETALSIDEAREA 2.07 LAYER Metal6  ;
    ANTENNAMODEL OXIDE1 ;
    ANTENNAGATEAREA 0.4662 LAYER Metal6  ;
    ANTENNAMAXAREACAR 9.58623 LAYER Metal6  ;
    ANTENNAMAXSIDEAREACAR 61.6396 LAYER Metal6  ;
    ANTENNAMAXCUTCAR 6.27756 LAYER Via6  ;
    PORT
      LAYER Metal6 ;
        RECT 74.260000 0.000000 74.340000 0.250000 ;
    END
  END result_o[7]
  PIN result_o[6]
    DIRECTION OUTPUT ;
    USE SIGNAL ;
    ANTENNADIFFAREA 3.1578 LAYER Metal6  ;
    ANTENNAPARTIALMETALAREA 1.1744 LAYER Metal6  ;
    ANTENNAPARTIALMETALSIDEAREA 5.2848 LAYER Metal6  ;
    ANTENNAMODEL OXIDE1 ;
    ANTENNAGATEAREA 0.4662 LAYER Metal6  ;
    ANTENNAMAXAREACAR 10.5009 LAYER Metal6  ;
    ANTENNAMAXSIDEAREACAR 65.7555 LAYER Metal6  ;
    ANTENNAMAXCUTCAR 6.27756 LAYER Via6  ;
    PORT
      LAYER Metal6 ;
        RECT 75.260000 0.000000 75.340000 0.250000 ;
    END
  END result_o[6]
  PIN result_o[5]
    DIRECTION OUTPUT ;
    USE SIGNAL ;
    ANTENNADIFFAREA 3.1578 LAYER Metal6  ;
    ANTENNAPARTIALMETALAREA 0.1712 LAYER Metal6  ;
    ANTENNAPARTIALMETALSIDEAREA 0.7704 LAYER Metal6  ;
    ANTENNAMODEL OXIDE1 ;
    ANTENNAGATEAREA 0.4662 LAYER Metal6  ;
    ANTENNAMAXAREACAR 8.73681 LAYER Metal6  ;
    ANTENNAMAXSIDEAREACAR 57.8172 LAYER Metal6  ;
    ANTENNAMAXCUTCAR 6.27756 LAYER Via6  ;
    PORT
      LAYER Metal6 ;
        RECT 76.260000 0.000000 76.340000 0.250000 ;
    END
  END result_o[5]
  PIN result_o[4]
    DIRECTION OUTPUT ;
    USE SIGNAL ;
    ANTENNADIFFAREA 3.1578 LAYER Metal6  ;
    ANTENNAPARTIALMETALAREA 0.7336 LAYER Metal6  ;
    ANTENNAPARTIALMETALSIDEAREA 3.3012 LAYER Metal6  ;
    ANTENNAMODEL OXIDE1 ;
    ANTENNAGATEAREA 0.4662 LAYER Metal6  ;
    ANTENNAMAXAREACAR 8.62527 LAYER Metal6  ;
    ANTENNAMAXSIDEAREACAR 57.3153 LAYER Metal6  ;
    ANTENNAMAXCUTCAR 6.27756 LAYER Via6  ;
    PORT
      LAYER Metal6 ;
        RECT 77.260000 0.000000 77.340000 0.250000 ;
    END
  END result_o[4]
  PIN result_o[3]
    DIRECTION OUTPUT ;
    USE SIGNAL ;
    ANTENNADIFFAREA 3.1578 LAYER Metal6  ;
    ANTENNAPARTIALMETALAREA 1.224 LAYER Metal6  ;
    ANTENNAPARTIALMETALSIDEAREA 5.508 LAYER Metal6  ;
    ANTENNAMODEL OXIDE1 ;
    ANTENNAGATEAREA 0.4662 LAYER Metal6  ;
    ANTENNAMAXAREACAR 9.61712 LAYER Metal6  ;
    ANTENNAMAXSIDEAREACAR 61.7786 LAYER Metal6  ;
    ANTENNAMAXCUTCAR 6.27756 LAYER Via6  ;
    PORT
      LAYER Metal6 ;
        RECT 78.260000 0.000000 78.340000 0.250000 ;
    END
  END result_o[3]
  PIN result_o[2]
    DIRECTION OUTPUT ;
    USE SIGNAL ;
    ANTENNADIFFAREA 3.1578 LAYER Metal6  ;
    ANTENNAPARTIALMETALAREA 0.6662 LAYER Metal6  ;
    ANTENNAPARTIALMETALSIDEAREA 2.9664 LAYER Metal6  ;
    ANTENNAMODEL OXIDE1 ;
    ANTENNAGATEAREA 0.4662 LAYER Metal6  ;
    ANTENNAMAXAREACAR 8.30223 LAYER Metal6  ;
    ANTENNAMAXSIDEAREACAR 55.7941 LAYER Metal6  ;
    ANTENNAMAXCUTCAR 6.27756 LAYER Via6  ;
    PORT
      LAYER Metal6 ;
        RECT 79.260000 0.000000 79.340000 0.250000 ;
    END
  END result_o[2]
  PIN result_o[1]
    DIRECTION OUTPUT ;
    USE SIGNAL ;
    ANTENNADIFFAREA 3.1578 LAYER Metal6  ;
    ANTENNAPARTIALMETALAREA 1.2788 LAYER Metal6  ;
    ANTENNAPARTIALMETALSIDEAREA 5.7546 LAYER Metal6  ;
    ANTENNAMODEL OXIDE1 ;
    ANTENNAGATEAREA 0.4662 LAYER Metal6  ;
    ANTENNAMAXAREACAR 9.80159 LAYER Metal6  ;
    ANTENNAMAXSIDEAREACAR 62.6088 LAYER Metal6  ;
    ANTENNAMAXCUTCAR 6.27756 LAYER Via6  ;
    PORT
      LAYER Metal6 ;
        RECT 80.260000 0.000000 80.340000 0.250000 ;
    END
  END result_o[1]
  PIN result_o[0]
    DIRECTION OUTPUT ;
    USE SIGNAL ;
    ANTENNADIFFAREA 3.1578 LAYER Metal6  ;
    ANTENNAPARTIALMETALAREA 0.996 LAYER Metal6  ;
    ANTENNAPARTIALMETALSIDEAREA 4.482 LAYER Metal6  ;
    ANTENNAMODEL OXIDE1 ;
    ANTENNAGATEAREA 0.4662 LAYER Metal6  ;
    ANTENNAMAXAREACAR 9.76469 LAYER Metal6  ;
    ANTENNAMAXSIDEAREACAR 62.4427 LAYER Metal6  ;
    ANTENNAMAXCUTCAR 6.27756 LAYER Via6  ;
    PORT
      LAYER Metal6 ;
        RECT 81.260000 0.000000 81.340000 0.250000 ;
    END
  END result_o[0]
  PIN scan_mode_matmul_sync
    DIRECTION INPUT ;
    USE SIGNAL ;
    PORT
      LAYER Metal5 ;
        RECT 0.000000 19.625000 0.250000 19.705000 ;
    END
  END scan_mode_matmul_sync
  PIN scan_enable_matmul_sync
    DIRECTION INPUT ;
    USE SIGNAL ;
    ANTENNAPARTIALMETALAREA 1.0124 LAYER Metal5  ;
    ANTENNAPARTIALMETALSIDEAREA 4.5558 LAYER Metal5  ;
    ANTENNAMODEL OXIDE1 ;
    ANTENNAGATEAREA 0.15255 LAYER Metal5  ;
    ANTENNAMAXAREACAR 12.008 LAYER Metal5  ;
    ANTENNAMAXSIDEAREACAR 64.1924 LAYER Metal5  ;
    ANTENNAMAXCUTCAR 2.16632 LAYER Via5  ;
    PORT
      LAYER Metal5 ;
        RECT 0.000000 18.675000 0.250000 18.755000 ;
    END
  END scan_enable_matmul_sync
  PIN scan_in_matmul_sync_0
    DIRECTION INPUT ;
    USE SIGNAL ;
    ANTENNAPARTIALMETALAREA 0.9956 LAYER Metal5  ;
    ANTENNAPARTIALMETALSIDEAREA 4.4802 LAYER Metal5  ;
    ANTENNAMODEL OXIDE1 ;
    ANTENNAGATEAREA 0.02925 LAYER Metal5  ;
    ANTENNAMAXAREACAR 38.906 LAYER Metal5  ;
    ANTENNAMAXSIDEAREACAR 177.99 LAYER Metal5  ;
    ANTENNAMAXCUTCAR 3.51453 LAYER Via5  ;
    PORT
      LAYER Metal5 ;
        RECT 0.000000 17.725000 0.250000 17.805000 ;
    END
  END scan_in_matmul_sync_0
  PIN scan_out_matmul_sync_0
    DIRECTION OUTPUT ;
    USE SIGNAL ;
    ANTENNADIFFAREA 3.1578 LAYER Metal6  ;
    ANTENNAPARTIALMETALAREA 0.7528 LAYER Metal6  ;
    ANTENNAPARTIALMETALSIDEAREA 3.3876 LAYER Metal6  ;
    ANTENNAMODEL OXIDE1 ;
    ANTENNAGATEAREA 0.4662 LAYER Metal6  ;
    ANTENNAMAXAREACAR 10.9762 LAYER Metal6  ;
    ANTENNAMAXSIDEAREACAR 67.8945 LAYER Metal6  ;
    ANTENNAMAXCUTCAR 6.27756 LAYER Via6  ;
    PORT
      LAYER Metal6 ;
        RECT 82.260000 0.000000 82.340000 0.250000 ;
    END
  END scan_out_matmul_sync_0
  PIN VDD
    DIRECTION INPUT ;
    USE POWER ;
    PORT
      LAYER Metal11 ;
        RECT 0.000000 84.440000 4.400000 88.840000 ;
    END
    PORT
      LAYER Metal11 ;
        RECT 96.600000 84.440000 101.000000 88.840000 ;
    END
    PORT
      LAYER Metal11 ;
        RECT 0.000000 68.290000 4.400000 72.690000 ;
    END
    PORT
      LAYER Metal11 ;
        RECT 96.600000 68.290000 101.000000 72.690000 ;
    END
    PORT
      LAYER Metal11 ;
        RECT 0.000000 52.615000 4.400000 57.015000 ;
    END
    PORT
      LAYER Metal11 ;
        RECT 96.600000 52.615000 101.000000 57.015000 ;
    END
    PORT
      LAYER Metal11 ;
        RECT 0.000000 36.465000 4.400000 40.865000 ;
    END
    PORT
      LAYER Metal11 ;
        RECT 96.600000 36.465000 101.000000 40.865000 ;
    END
    PORT
      LAYER Metal11 ;
        RECT 0.000000 20.315000 4.400000 24.715000 ;
    END
    PORT
      LAYER Metal11 ;
        RECT 96.600000 20.315000 101.000000 24.715000 ;
    END
    PORT
      LAYER Metal11 ;
        RECT 0.000000 4.165000 4.400000 8.565000 ;
    END
    PORT
      LAYER Metal11 ;
        RECT 96.600000 4.165000 101.000000 8.565000 ;
    END
    PORT
      LAYER Metal10 ;
        RECT 84.400000 0.000000 88.800000 4.400000 ;
    END
    PORT
      LAYER Metal10 ;
        RECT 84.400000 98.200000 88.800000 102.600000 ;
    END
    PORT
      LAYER Metal10 ;
        RECT 68.400000 0.000000 72.800000 4.400000 ;
    END
    PORT
      LAYER Metal10 ;
        RECT 68.400000 98.200000 72.800000 102.600000 ;
    END
    PORT
      LAYER Metal10 ;
        RECT 52.400000 0.000000 56.800000 4.400000 ;
    END
    PORT
      LAYER Metal10 ;
        RECT 52.400000 98.200000 56.800000 102.600000 ;
    END
    PORT
      LAYER Metal10 ;
        RECT 36.400000 0.000000 40.800000 4.400000 ;
    END
    PORT
      LAYER Metal10 ;
        RECT 36.400000 98.200000 40.800000 102.600000 ;
    END
    PORT
      LAYER Metal10 ;
        RECT 20.400000 0.000000 24.800000 4.400000 ;
    END
    PORT
      LAYER Metal10 ;
        RECT 20.400000 98.200000 24.800000 102.600000 ;
    END
    PORT
      LAYER Metal10 ;
        RECT 4.400000 0.000000 8.800000 4.400000 ;
    END
    PORT
      LAYER Metal10 ;
        RECT 4.400000 98.200000 8.800000 102.600000 ;
    END
    PORT
      LAYER Metal9 ;
        RECT 0.000000 100.445000 0.320000 100.765000 ;
    END
    PORT
      LAYER Metal9 ;
        RECT 100.680000 100.445000 101.000000 100.765000 ;
    END
    PORT
      LAYER Metal9 ;
        RECT 0.000000 84.485000 0.320000 84.805000 ;
    END
    PORT
      LAYER Metal9 ;
        RECT 100.680000 84.485000 101.000000 84.805000 ;
    END
    PORT
      LAYER Metal9 ;
        RECT 0.000000 68.335000 0.320000 68.655000 ;
    END
    PORT
      LAYER Metal9 ;
        RECT 100.680000 68.335000 101.000000 68.655000 ;
    END
    PORT
      LAYER Metal9 ;
        RECT 0.000000 52.375000 0.320000 52.695000 ;
    END
    PORT
      LAYER Metal9 ;
        RECT 100.680000 52.375000 101.000000 52.695000 ;
    END
    PORT
      LAYER Metal9 ;
        RECT 0.000000 36.415000 0.320000 36.735000 ;
    END
    PORT
      LAYER Metal9 ;
        RECT 100.680000 36.415000 101.000000 36.735000 ;
    END
    PORT
      LAYER Metal9 ;
        RECT 0.000000 20.455000 0.320000 20.775000 ;
    END
    PORT
      LAYER Metal9 ;
        RECT 100.680000 20.455000 101.000000 20.775000 ;
    END
    PORT
      LAYER Metal9 ;
        RECT 0.000000 4.495000 0.320000 4.815000 ;
    END
    PORT
      LAYER Metal9 ;
        RECT 100.680000 4.495000 101.000000 4.815000 ;
    END
    PORT
      LAYER Metal8 ;
        RECT 100.340000 0.000000 100.660000 0.320000 ;
    END
    PORT
      LAYER Metal8 ;
        RECT 100.340000 102.280000 100.660000 102.600000 ;
    END
    PORT
      LAYER Metal8 ;
        RECT 84.340000 0.000000 84.660000 0.320000 ;
    END
    PORT
      LAYER Metal8 ;
        RECT 84.340000 102.280000 84.660000 102.600000 ;
    END
    PORT
      LAYER Metal8 ;
        RECT 68.340000 0.000000 68.660000 0.320000 ;
    END
    PORT
      LAYER Metal8 ;
        RECT 68.340000 102.280000 68.660000 102.600000 ;
    END
    PORT
      LAYER Metal8 ;
        RECT 52.340000 0.000000 52.660000 0.320000 ;
    END
    PORT
      LAYER Metal8 ;
        RECT 52.340000 102.280000 52.660000 102.600000 ;
    END
    PORT
      LAYER Metal8 ;
        RECT 36.340000 0.000000 36.660000 0.320000 ;
    END
    PORT
      LAYER Metal8 ;
        RECT 36.340000 102.280000 36.660000 102.600000 ;
    END
    PORT
      LAYER Metal8 ;
        RECT 20.340000 0.000000 20.660000 0.320000 ;
    END
    PORT
      LAYER Metal8 ;
        RECT 20.340000 102.280000 20.660000 102.600000 ;
    END
    PORT
      LAYER Metal8 ;
        RECT 4.340000 0.000000 4.660000 0.320000 ;
    END
    PORT
      LAYER Metal8 ;
        RECT 4.340000 102.280000 4.660000 102.600000 ;
    END
    PORT
      LAYER Metal7 ;
        RECT 0.000000 100.445000 0.320000 100.765000 ;
    END
    PORT
      LAYER Metal7 ;
        RECT 100.680000 100.445000 101.000000 100.765000 ;
    END
    PORT
      LAYER Metal7 ;
        RECT 0.000000 84.485000 0.320000 84.805000 ;
    END
    PORT
      LAYER Metal7 ;
        RECT 100.680000 84.485000 101.000000 84.805000 ;
    END
    PORT
      LAYER Metal7 ;
        RECT 0.000000 68.335000 0.320000 68.655000 ;
    END
    PORT
      LAYER Metal7 ;
        RECT 100.680000 68.335000 101.000000 68.655000 ;
    END
    PORT
      LAYER Metal7 ;
        RECT 0.000000 52.375000 0.320000 52.695000 ;
    END
    PORT
      LAYER Metal7 ;
        RECT 100.680000 52.375000 101.000000 52.695000 ;
    END
    PORT
      LAYER Metal7 ;
        RECT 0.000000 36.415000 0.320000 36.735000 ;
    END
    PORT
      LAYER Metal7 ;
        RECT 100.680000 36.415000 101.000000 36.735000 ;
    END
    PORT
      LAYER Metal7 ;
        RECT 0.000000 20.455000 0.320000 20.775000 ;
    END
    PORT
      LAYER Metal7 ;
        RECT 100.680000 20.455000 101.000000 20.775000 ;
    END
    PORT
      LAYER Metal7 ;
        RECT 0.000000 4.495000 0.320000 4.815000 ;
    END
    PORT
      LAYER Metal7 ;
        RECT 100.680000 4.495000 101.000000 4.815000 ;
    END
    PORT
      LAYER Metal6 ;
        RECT 100.340000 0.000000 100.660000 0.320000 ;
    END
    PORT
      LAYER Metal6 ;
        RECT 100.340000 102.280000 100.660000 102.600000 ;
    END
    PORT
      LAYER Metal6 ;
        RECT 84.340000 0.000000 84.660000 0.320000 ;
    END
    PORT
      LAYER Metal6 ;
        RECT 84.340000 102.280000 84.660000 102.600000 ;
    END
    PORT
      LAYER Metal6 ;
        RECT 68.340000 102.280000 68.660000 102.600000 ;
    END
    PORT
      LAYER Metal6 ;
        RECT 52.340000 102.280000 52.660000 102.600000 ;
    END
    PORT
      LAYER Metal6 ;
        RECT 36.340000 102.280000 36.660000 102.600000 ;
    END
    PORT
      LAYER Metal6 ;
        RECT 20.340000 102.280000 20.660000 102.600000 ;
    END
    PORT
      LAYER Metal6 ;
        RECT 4.340000 0.000000 4.660000 0.320000 ;
    END
    PORT
      LAYER Metal6 ;
        RECT 4.340000 102.280000 4.660000 102.600000 ;
    END

# P/G power stripe data as pin
    PORT
      LAYER Metal10 ;
        RECT 4.400000 0.000000 8.800000 102.600000 ;
        RECT 20.400000 0.000000 24.800000 102.600000 ;
        RECT 36.400000 0.000000 40.800000 102.600000 ;
        RECT 52.400000 0.000000 56.800000 102.600000 ;
        RECT 68.400000 0.000000 72.800000 102.600000 ;
        RECT 84.400000 0.000000 88.800000 102.600000 ;
    END
# end of P/G power stripe data as pin

  END VDD
  PIN VSS
    DIRECTION INPUT ;
    USE GROUND ;
    PORT
      LAYER Metal11 ;
        RECT 0.000000 92.515000 4.400000 96.915000 ;
    END
    PORT
      LAYER Metal11 ;
        RECT 96.600000 92.515000 101.000000 96.915000 ;
    END
    PORT
      LAYER Metal11 ;
        RECT 0.000000 76.365000 4.400000 80.765000 ;
    END
    PORT
      LAYER Metal11 ;
        RECT 96.600000 76.365000 101.000000 80.765000 ;
    END
    PORT
      LAYER Metal11 ;
        RECT 0.000000 60.690000 4.400000 65.090000 ;
    END
    PORT
      LAYER Metal11 ;
        RECT 96.600000 60.690000 101.000000 65.090000 ;
    END
    PORT
      LAYER Metal11 ;
        RECT 0.000000 44.540000 4.400000 48.940000 ;
    END
    PORT
      LAYER Metal11 ;
        RECT 96.600000 44.540000 101.000000 48.940000 ;
    END
    PORT
      LAYER Metal11 ;
        RECT 0.000000 28.390000 4.400000 32.790000 ;
    END
    PORT
      LAYER Metal11 ;
        RECT 96.600000 28.390000 101.000000 32.790000 ;
    END
    PORT
      LAYER Metal11 ;
        RECT 0.000000 12.715000 4.400000 17.115000 ;
    END
    PORT
      LAYER Metal11 ;
        RECT 96.600000 12.715000 101.000000 17.115000 ;
    END
    PORT
      LAYER Metal10 ;
        RECT 92.400000 0.000000 96.800000 4.400000 ;
    END
    PORT
      LAYER Metal10 ;
        RECT 92.400000 98.200000 96.800000 102.600000 ;
    END
    PORT
      LAYER Metal10 ;
        RECT 76.400000 0.000000 80.800000 4.400000 ;
    END
    PORT
      LAYER Metal10 ;
        RECT 76.400000 98.200000 80.800000 102.600000 ;
    END
    PORT
      LAYER Metal10 ;
        RECT 60.400000 0.000000 64.800000 4.400000 ;
    END
    PORT
      LAYER Metal10 ;
        RECT 60.400000 98.200000 64.800000 102.600000 ;
    END
    PORT
      LAYER Metal10 ;
        RECT 44.400000 0.000000 48.800000 4.400000 ;
    END
    PORT
      LAYER Metal10 ;
        RECT 44.400000 98.200000 48.800000 102.600000 ;
    END
    PORT
      LAYER Metal10 ;
        RECT 28.400000 0.000000 32.800000 4.400000 ;
    END
    PORT
      LAYER Metal10 ;
        RECT 28.400000 98.200000 32.800000 102.600000 ;
    END
    PORT
      LAYER Metal10 ;
        RECT 12.400000 0.000000 16.800000 4.400000 ;
    END
    PORT
      LAYER Metal10 ;
        RECT 12.400000 98.200000 16.800000 102.600000 ;
    END
    PORT
      LAYER Metal9 ;
        RECT 0.000000 96.075000 0.320000 96.395000 ;
    END
    PORT
      LAYER Metal9 ;
        RECT 100.680000 96.075000 101.000000 96.395000 ;
    END
    PORT
      LAYER Metal9 ;
        RECT 0.000000 80.115000 0.320000 80.435000 ;
    END
    PORT
      LAYER Metal9 ;
        RECT 100.680000 80.115000 101.000000 80.435000 ;
    END
    PORT
      LAYER Metal9 ;
        RECT 0.000000 64.155000 0.320000 64.475000 ;
    END
    PORT
      LAYER Metal9 ;
        RECT 100.680000 64.155000 101.000000 64.475000 ;
    END
    PORT
      LAYER Metal9 ;
        RECT 0.000000 48.195000 0.320000 48.515000 ;
    END
    PORT
      LAYER Metal9 ;
        RECT 100.680000 48.195000 101.000000 48.515000 ;
    END
    PORT
      LAYER Metal9 ;
        RECT 0.000000 32.045000 0.320000 32.365000 ;
    END
    PORT
      LAYER Metal9 ;
        RECT 100.680000 32.045000 101.000000 32.365000 ;
    END
    PORT
      LAYER Metal9 ;
        RECT 0.000000 16.085000 0.320000 16.405000 ;
    END
    PORT
      LAYER Metal9 ;
        RECT 100.680000 16.085000 101.000000 16.405000 ;
    END
    PORT
      LAYER Metal8 ;
        RECT 96.140000 0.000000 96.460000 0.320000 ;
    END
    PORT
      LAYER Metal8 ;
        RECT 96.140000 102.280000 96.460000 102.600000 ;
    END
    PORT
      LAYER Metal8 ;
        RECT 80.140000 0.000000 80.460000 0.320000 ;
    END
    PORT
      LAYER Metal8 ;
        RECT 80.140000 102.280000 80.460000 102.600000 ;
    END
    PORT
      LAYER Metal8 ;
        RECT 64.140000 0.000000 64.460000 0.320000 ;
    END
    PORT
      LAYER Metal8 ;
        RECT 64.140000 102.280000 64.460000 102.600000 ;
    END
    PORT
      LAYER Metal8 ;
        RECT 48.140000 0.000000 48.460000 0.320000 ;
    END
    PORT
      LAYER Metal8 ;
        RECT 48.140000 102.280000 48.460000 102.600000 ;
    END
    PORT
      LAYER Metal8 ;
        RECT 32.140000 0.000000 32.460000 0.320000 ;
    END
    PORT
      LAYER Metal8 ;
        RECT 32.140000 102.280000 32.460000 102.600000 ;
    END
    PORT
      LAYER Metal8 ;
        RECT 16.140000 0.000000 16.460000 0.320000 ;
    END
    PORT
      LAYER Metal8 ;
        RECT 16.140000 102.280000 16.460000 102.600000 ;
    END
    PORT
      LAYER Metal7 ;
        RECT 0.000000 96.075000 0.320000 96.395000 ;
    END
    PORT
      LAYER Metal7 ;
        RECT 100.680000 96.075000 101.000000 96.395000 ;
    END
    PORT
      LAYER Metal7 ;
        RECT 0.000000 80.115000 0.320000 80.435000 ;
    END
    PORT
      LAYER Metal7 ;
        RECT 100.680000 80.115000 101.000000 80.435000 ;
    END
    PORT
      LAYER Metal7 ;
        RECT 0.000000 64.155000 0.320000 64.475000 ;
    END
    PORT
      LAYER Metal7 ;
        RECT 100.680000 64.155000 101.000000 64.475000 ;
    END
    PORT
      LAYER Metal7 ;
        RECT 0.000000 48.195000 0.320000 48.515000 ;
    END
    PORT
      LAYER Metal7 ;
        RECT 100.680000 48.195000 101.000000 48.515000 ;
    END
    PORT
      LAYER Metal7 ;
        RECT 0.000000 32.045000 0.320000 32.365000 ;
    END
    PORT
      LAYER Metal7 ;
        RECT 100.680000 32.045000 101.000000 32.365000 ;
    END
    PORT
      LAYER Metal7 ;
        RECT 0.000000 16.085000 0.320000 16.405000 ;
    END
    PORT
      LAYER Metal7 ;
        RECT 100.680000 16.085000 101.000000 16.405000 ;
    END
    PORT
      LAYER Metal6 ;
        RECT 96.140000 0.000000 96.460000 0.320000 ;
    END
    PORT
      LAYER Metal6 ;
        RECT 96.140000 102.280000 96.460000 102.600000 ;
    END
    PORT
      LAYER Metal6 ;
        RECT 80.140000 102.280000 80.460000 102.600000 ;
    END
    PORT
      LAYER Metal6 ;
        RECT 64.140000 102.280000 64.460000 102.600000 ;
    END
    PORT
      LAYER Metal6 ;
        RECT 48.140000 102.280000 48.460000 102.600000 ;
    END
    PORT
      LAYER Metal6 ;
        RECT 32.140000 102.280000 32.460000 102.600000 ;
    END
    PORT
      LAYER Metal6 ;
        RECT 16.140000 0.000000 16.460000 0.320000 ;
    END
    PORT
      LAYER Metal6 ;
        RECT 16.140000 102.280000 16.460000 102.600000 ;
    END

# P/G power stripe data as pin
    PORT
      LAYER Metal10 ;
        RECT 12.400000 0.000000 16.800000 102.600000 ;
        RECT 28.400000 0.000000 32.800000 102.600000 ;
        RECT 44.400000 0.000000 48.800000 102.600000 ;
        RECT 60.400000 0.000000 64.800000 102.600000 ;
        RECT 76.400000 0.000000 80.800000 102.600000 ;
        RECT 92.400000 0.000000 96.800000 102.600000 ;
    END
# end of P/G power stripe data as pin

  END VSS
  OBS
    LAYER Metal1 ;
      RECT 0.000000 0.000000 101.000000 102.600000 ;
    LAYER Metal2 ;
      RECT 0.000000 0.000000 101.000000 102.600000 ;
    LAYER Metal3 ;
      RECT 0.000000 0.000000 101.000000 102.600000 ;
    LAYER Metal4 ;
      RECT 0.000000 0.000000 101.000000 102.600000 ;
    LAYER Metal5 ;
      RECT 0.000000 82.475000 101.000000 102.600000 ;
      RECT 0.330000 82.255000 101.000000 82.475000 ;
      RECT 0.000000 81.525000 101.000000 82.255000 ;
      RECT 0.330000 81.305000 101.000000 81.525000 ;
      RECT 0.000000 80.575000 101.000000 81.305000 ;
      RECT 0.330000 80.355000 101.000000 80.575000 ;
      RECT 0.000000 79.625000 101.000000 80.355000 ;
      RECT 0.330000 79.405000 101.000000 79.625000 ;
      RECT 0.000000 78.675000 101.000000 79.405000 ;
      RECT 0.330000 78.455000 101.000000 78.675000 ;
      RECT 0.000000 77.725000 101.000000 78.455000 ;
      RECT 0.330000 77.505000 101.000000 77.725000 ;
      RECT 0.000000 76.775000 101.000000 77.505000 ;
      RECT 0.330000 76.555000 101.000000 76.775000 ;
      RECT 0.000000 75.825000 101.000000 76.555000 ;
      RECT 0.330000 75.605000 101.000000 75.825000 ;
      RECT 0.000000 74.875000 101.000000 75.605000 ;
      RECT 0.330000 74.655000 101.000000 74.875000 ;
      RECT 0.000000 73.925000 101.000000 74.655000 ;
      RECT 0.330000 73.705000 101.000000 73.925000 ;
      RECT 0.000000 72.975000 101.000000 73.705000 ;
      RECT 0.330000 72.755000 101.000000 72.975000 ;
      RECT 0.000000 72.025000 101.000000 72.755000 ;
      RECT 0.330000 71.805000 101.000000 72.025000 ;
      RECT 0.000000 71.075000 101.000000 71.805000 ;
      RECT 0.330000 70.855000 101.000000 71.075000 ;
      RECT 0.000000 70.125000 101.000000 70.855000 ;
      RECT 0.330000 69.905000 101.000000 70.125000 ;
      RECT 0.000000 69.175000 101.000000 69.905000 ;
      RECT 0.330000 68.955000 101.000000 69.175000 ;
      RECT 0.000000 68.225000 101.000000 68.955000 ;
      RECT 0.330000 68.005000 101.000000 68.225000 ;
      RECT 0.000000 67.275000 101.000000 68.005000 ;
      RECT 0.330000 67.055000 101.000000 67.275000 ;
      RECT 0.000000 66.325000 101.000000 67.055000 ;
      RECT 0.330000 66.105000 101.000000 66.325000 ;
      RECT 0.000000 65.375000 101.000000 66.105000 ;
      RECT 0.330000 65.155000 101.000000 65.375000 ;
      RECT 0.000000 64.425000 101.000000 65.155000 ;
      RECT 0.330000 64.205000 101.000000 64.425000 ;
      RECT 0.000000 63.475000 101.000000 64.205000 ;
      RECT 0.330000 63.255000 101.000000 63.475000 ;
      RECT 0.000000 62.525000 101.000000 63.255000 ;
      RECT 0.330000 62.305000 101.000000 62.525000 ;
      RECT 0.000000 61.575000 101.000000 62.305000 ;
      RECT 0.330000 61.355000 101.000000 61.575000 ;
      RECT 0.000000 60.625000 101.000000 61.355000 ;
      RECT 0.330000 60.405000 101.000000 60.625000 ;
      RECT 0.000000 59.675000 101.000000 60.405000 ;
      RECT 0.330000 59.455000 101.000000 59.675000 ;
      RECT 0.000000 58.725000 101.000000 59.455000 ;
      RECT 0.330000 58.505000 101.000000 58.725000 ;
      RECT 0.000000 57.775000 101.000000 58.505000 ;
      RECT 0.330000 57.555000 101.000000 57.775000 ;
      RECT 0.000000 56.825000 101.000000 57.555000 ;
      RECT 0.330000 56.605000 101.000000 56.825000 ;
      RECT 0.000000 55.875000 101.000000 56.605000 ;
      RECT 0.330000 55.655000 101.000000 55.875000 ;
      RECT 0.000000 54.925000 101.000000 55.655000 ;
      RECT 0.330000 54.705000 101.000000 54.925000 ;
      RECT 0.000000 53.975000 101.000000 54.705000 ;
      RECT 0.330000 53.755000 101.000000 53.975000 ;
      RECT 0.000000 53.025000 101.000000 53.755000 ;
      RECT 0.330000 52.805000 101.000000 53.025000 ;
      RECT 0.000000 52.075000 101.000000 52.805000 ;
      RECT 0.330000 51.855000 101.000000 52.075000 ;
      RECT 0.000000 51.125000 101.000000 51.855000 ;
      RECT 0.330000 50.905000 101.000000 51.125000 ;
      RECT 0.000000 50.175000 101.000000 50.905000 ;
      RECT 0.330000 49.955000 101.000000 50.175000 ;
      RECT 0.000000 49.225000 101.000000 49.955000 ;
      RECT 0.330000 49.005000 101.000000 49.225000 ;
      RECT 0.000000 48.275000 101.000000 49.005000 ;
      RECT 0.330000 48.055000 101.000000 48.275000 ;
      RECT 0.000000 47.325000 101.000000 48.055000 ;
      RECT 0.330000 47.105000 101.000000 47.325000 ;
      RECT 0.000000 46.375000 101.000000 47.105000 ;
      RECT 0.330000 46.155000 101.000000 46.375000 ;
      RECT 0.000000 45.425000 101.000000 46.155000 ;
      RECT 0.330000 45.205000 101.000000 45.425000 ;
      RECT 0.000000 44.475000 101.000000 45.205000 ;
      RECT 0.330000 44.255000 101.000000 44.475000 ;
      RECT 0.000000 43.525000 101.000000 44.255000 ;
      RECT 0.330000 43.305000 101.000000 43.525000 ;
      RECT 0.000000 42.575000 101.000000 43.305000 ;
      RECT 0.330000 42.355000 101.000000 42.575000 ;
      RECT 0.000000 41.625000 101.000000 42.355000 ;
      RECT 0.330000 41.405000 101.000000 41.625000 ;
      RECT 0.000000 40.675000 101.000000 41.405000 ;
      RECT 0.330000 40.455000 101.000000 40.675000 ;
      RECT 0.000000 39.725000 101.000000 40.455000 ;
      RECT 0.330000 39.505000 101.000000 39.725000 ;
      RECT 0.000000 38.775000 101.000000 39.505000 ;
      RECT 0.330000 38.555000 101.000000 38.775000 ;
      RECT 0.000000 37.825000 101.000000 38.555000 ;
      RECT 0.330000 37.605000 101.000000 37.825000 ;
      RECT 0.000000 36.875000 101.000000 37.605000 ;
      RECT 0.330000 36.655000 101.000000 36.875000 ;
      RECT 0.000000 35.925000 101.000000 36.655000 ;
      RECT 0.330000 35.705000 101.000000 35.925000 ;
      RECT 0.000000 34.975000 101.000000 35.705000 ;
      RECT 0.330000 34.755000 101.000000 34.975000 ;
      RECT 0.000000 34.025000 101.000000 34.755000 ;
      RECT 0.330000 33.805000 101.000000 34.025000 ;
      RECT 0.000000 33.075000 101.000000 33.805000 ;
      RECT 0.330000 32.855000 101.000000 33.075000 ;
      RECT 0.000000 32.125000 101.000000 32.855000 ;
      RECT 0.330000 31.905000 101.000000 32.125000 ;
      RECT 0.000000 31.175000 101.000000 31.905000 ;
      RECT 0.330000 30.955000 101.000000 31.175000 ;
      RECT 0.000000 30.225000 101.000000 30.955000 ;
      RECT 0.330000 30.005000 101.000000 30.225000 ;
      RECT 0.000000 29.275000 101.000000 30.005000 ;
      RECT 0.330000 29.055000 101.000000 29.275000 ;
      RECT 0.000000 28.325000 101.000000 29.055000 ;
      RECT 0.330000 28.105000 101.000000 28.325000 ;
      RECT 0.000000 27.375000 101.000000 28.105000 ;
      RECT 0.330000 27.155000 101.000000 27.375000 ;
      RECT 0.000000 26.425000 101.000000 27.155000 ;
      RECT 0.330000 26.205000 101.000000 26.425000 ;
      RECT 0.000000 25.475000 101.000000 26.205000 ;
      RECT 0.330000 25.255000 101.000000 25.475000 ;
      RECT 0.000000 24.525000 101.000000 25.255000 ;
      RECT 0.330000 24.305000 101.000000 24.525000 ;
      RECT 0.000000 23.575000 101.000000 24.305000 ;
      RECT 0.330000 23.355000 101.000000 23.575000 ;
      RECT 0.000000 22.625000 101.000000 23.355000 ;
      RECT 0.330000 22.405000 101.000000 22.625000 ;
      RECT 0.000000 21.675000 101.000000 22.405000 ;
      RECT 0.330000 21.455000 101.000000 21.675000 ;
      RECT 0.000000 20.725000 101.000000 21.455000 ;
      RECT 0.330000 20.505000 101.000000 20.725000 ;
      RECT 0.000000 19.775000 101.000000 20.505000 ;
      RECT 0.330000 19.555000 101.000000 19.775000 ;
      RECT 0.000000 18.825000 101.000000 19.555000 ;
      RECT 0.330000 18.605000 101.000000 18.825000 ;
      RECT 0.000000 17.875000 101.000000 18.605000 ;
      RECT 0.330000 17.655000 101.000000 17.875000 ;
      RECT 0.000000 0.000000 101.000000 17.655000 ;
    LAYER Metal6 ;
      RECT 100.810000 102.130000 101.000000 102.600000 ;
      RECT 96.610000 102.130000 100.190000 102.600000 ;
      RECT 84.810000 102.130000 95.990000 102.600000 ;
      RECT 80.610000 102.130000 84.190000 102.600000 ;
      RECT 68.810000 102.130000 79.990000 102.600000 ;
      RECT 64.610000 102.130000 68.190000 102.600000 ;
      RECT 52.810000 102.130000 63.990000 102.600000 ;
      RECT 48.610000 102.130000 52.190000 102.600000 ;
      RECT 36.810000 102.130000 47.990000 102.600000 ;
      RECT 32.610000 102.130000 36.190000 102.600000 ;
      RECT 20.810000 102.130000 31.990000 102.600000 ;
      RECT 16.610000 102.130000 20.190000 102.600000 ;
      RECT 4.810000 102.130000 15.990000 102.600000 ;
      RECT 0.000000 102.130000 4.190000 102.600000 ;
      RECT 0.000000 0.470000 101.000000 102.130000 ;
      RECT 16.610000 0.330000 84.190000 0.470000 ;
      RECT 100.810000 0.000000 101.000000 0.470000 ;
      RECT 96.610000 0.000000 100.190000 0.470000 ;
      RECT 84.810000 0.000000 95.990000 0.470000 ;
      RECT 82.410000 0.000000 84.190000 0.330000 ;
      RECT 81.410000 0.000000 82.190000 0.330000 ;
      RECT 80.410000 0.000000 81.190000 0.330000 ;
      RECT 79.410000 0.000000 80.190000 0.330000 ;
      RECT 78.410000 0.000000 79.190000 0.330000 ;
      RECT 77.410000 0.000000 78.190000 0.330000 ;
      RECT 76.410000 0.000000 77.190000 0.330000 ;
      RECT 75.410000 0.000000 76.190000 0.330000 ;
      RECT 74.410000 0.000000 75.190000 0.330000 ;
      RECT 73.410000 0.000000 74.190000 0.330000 ;
      RECT 72.410000 0.000000 73.190000 0.330000 ;
      RECT 71.410000 0.000000 72.190000 0.330000 ;
      RECT 70.410000 0.000000 71.190000 0.330000 ;
      RECT 69.410000 0.000000 70.190000 0.330000 ;
      RECT 68.410000 0.000000 69.190000 0.330000 ;
      RECT 67.410000 0.000000 68.190000 0.330000 ;
      RECT 66.410000 0.000000 67.190000 0.330000 ;
      RECT 65.410000 0.000000 66.190000 0.330000 ;
      RECT 64.410000 0.000000 65.190000 0.330000 ;
      RECT 63.410000 0.000000 64.190000 0.330000 ;
      RECT 62.410000 0.000000 63.190000 0.330000 ;
      RECT 61.410000 0.000000 62.190000 0.330000 ;
      RECT 60.410000 0.000000 61.190000 0.330000 ;
      RECT 59.410000 0.000000 60.190000 0.330000 ;
      RECT 58.410000 0.000000 59.190000 0.330000 ;
      RECT 57.410000 0.000000 58.190000 0.330000 ;
      RECT 56.410000 0.000000 57.190000 0.330000 ;
      RECT 55.410000 0.000000 56.190000 0.330000 ;
      RECT 54.410000 0.000000 55.190000 0.330000 ;
      RECT 53.410000 0.000000 54.190000 0.330000 ;
      RECT 52.410000 0.000000 53.190000 0.330000 ;
      RECT 51.410000 0.000000 52.190000 0.330000 ;
      RECT 50.410000 0.000000 51.190000 0.330000 ;
      RECT 49.410000 0.000000 50.190000 0.330000 ;
      RECT 48.410000 0.000000 49.190000 0.330000 ;
      RECT 47.410000 0.000000 48.190000 0.330000 ;
      RECT 46.410000 0.000000 47.190000 0.330000 ;
      RECT 45.410000 0.000000 46.190000 0.330000 ;
      RECT 44.410000 0.000000 45.190000 0.330000 ;
      RECT 43.410000 0.000000 44.190000 0.330000 ;
      RECT 42.410000 0.000000 43.190000 0.330000 ;
      RECT 41.410000 0.000000 42.190000 0.330000 ;
      RECT 40.410000 0.000000 41.190000 0.330000 ;
      RECT 39.410000 0.000000 40.190000 0.330000 ;
      RECT 38.410000 0.000000 39.190000 0.330000 ;
      RECT 37.410000 0.000000 38.190000 0.330000 ;
      RECT 36.410000 0.000000 37.190000 0.330000 ;
      RECT 35.410000 0.000000 36.190000 0.330000 ;
      RECT 34.410000 0.000000 35.190000 0.330000 ;
      RECT 33.410000 0.000000 34.190000 0.330000 ;
      RECT 32.410000 0.000000 33.190000 0.330000 ;
      RECT 31.410000 0.000000 32.190000 0.330000 ;
      RECT 30.410000 0.000000 31.190000 0.330000 ;
      RECT 29.410000 0.000000 30.190000 0.330000 ;
      RECT 28.410000 0.000000 29.190000 0.330000 ;
      RECT 27.410000 0.000000 28.190000 0.330000 ;
      RECT 26.410000 0.000000 27.190000 0.330000 ;
      RECT 25.410000 0.000000 26.190000 0.330000 ;
      RECT 24.410000 0.000000 25.190000 0.330000 ;
      RECT 23.410000 0.000000 24.190000 0.330000 ;
      RECT 22.410000 0.000000 23.190000 0.330000 ;
      RECT 21.410000 0.000000 22.190000 0.330000 ;
      RECT 20.410000 0.000000 21.190000 0.330000 ;
      RECT 19.410000 0.000000 20.190000 0.330000 ;
      RECT 18.410000 0.000000 19.190000 0.330000 ;
      RECT 16.610000 0.000000 18.190000 0.330000 ;
      RECT 4.810000 0.000000 15.990000 0.470000 ;
      RECT 0.000000 0.000000 4.190000 0.470000 ;
    LAYER Metal7 ;
      RECT 0.000000 100.915000 101.000000 102.600000 ;
      RECT 0.470000 100.295000 100.530000 100.915000 ;
      RECT 0.000000 96.545000 101.000000 100.295000 ;
      RECT 0.470000 95.925000 100.530000 96.545000 ;
      RECT 0.000000 84.955000 101.000000 95.925000 ;
      RECT 0.470000 84.335000 100.530000 84.955000 ;
      RECT 0.000000 80.585000 101.000000 84.335000 ;
      RECT 0.470000 79.965000 100.530000 80.585000 ;
      RECT 0.000000 68.805000 101.000000 79.965000 ;
      RECT 0.470000 68.185000 100.530000 68.805000 ;
      RECT 0.000000 64.625000 101.000000 68.185000 ;
      RECT 0.470000 64.005000 100.530000 64.625000 ;
      RECT 0.000000 52.845000 101.000000 64.005000 ;
      RECT 0.470000 52.225000 100.530000 52.845000 ;
      RECT 0.000000 48.665000 101.000000 52.225000 ;
      RECT 0.470000 48.045000 100.530000 48.665000 ;
      RECT 0.000000 36.885000 101.000000 48.045000 ;
      RECT 0.470000 36.265000 100.530000 36.885000 ;
      RECT 0.000000 32.515000 101.000000 36.265000 ;
      RECT 0.470000 31.895000 100.530000 32.515000 ;
      RECT 0.000000 20.925000 101.000000 31.895000 ;
      RECT 0.470000 20.305000 100.530000 20.925000 ;
      RECT 0.000000 16.555000 101.000000 20.305000 ;
      RECT 0.470000 15.935000 100.530000 16.555000 ;
      RECT 0.000000 4.965000 101.000000 15.935000 ;
      RECT 0.470000 4.345000 100.530000 4.965000 ;
      RECT 0.000000 0.000000 101.000000 4.345000 ;
    LAYER Metal8 ;
      RECT 100.810000 102.130000 101.000000 102.600000 ;
      RECT 96.610000 102.130000 100.190000 102.600000 ;
      RECT 84.810000 102.130000 95.990000 102.600000 ;
      RECT 80.610000 102.130000 84.190000 102.600000 ;
      RECT 68.810000 102.130000 79.990000 102.600000 ;
      RECT 64.610000 102.130000 68.190000 102.600000 ;
      RECT 52.810000 102.130000 63.990000 102.600000 ;
      RECT 48.610000 102.130000 52.190000 102.600000 ;
      RECT 36.810000 102.130000 47.990000 102.600000 ;
      RECT 32.610000 102.130000 36.190000 102.600000 ;
      RECT 20.810000 102.130000 31.990000 102.600000 ;
      RECT 16.610000 102.130000 20.190000 102.600000 ;
      RECT 4.810000 102.130000 15.990000 102.600000 ;
      RECT 0.000000 102.130000 4.190000 102.600000 ;
      RECT 0.000000 0.470000 101.000000 102.130000 ;
      RECT 100.810000 0.000000 101.000000 0.470000 ;
      RECT 96.610000 0.000000 100.190000 0.470000 ;
      RECT 84.810000 0.000000 95.990000 0.470000 ;
      RECT 80.610000 0.000000 84.190000 0.470000 ;
      RECT 68.810000 0.000000 79.990000 0.470000 ;
      RECT 64.610000 0.000000 68.190000 0.470000 ;
      RECT 52.810000 0.000000 63.990000 0.470000 ;
      RECT 48.610000 0.000000 52.190000 0.470000 ;
      RECT 36.810000 0.000000 47.990000 0.470000 ;
      RECT 32.610000 0.000000 36.190000 0.470000 ;
      RECT 20.810000 0.000000 31.990000 0.470000 ;
      RECT 16.610000 0.000000 20.190000 0.470000 ;
      RECT 4.810000 0.000000 15.990000 0.470000 ;
      RECT 0.000000 0.000000 4.190000 0.470000 ;
    LAYER Metal9 ;
      RECT 0.000000 100.915000 101.000000 102.600000 ;
      RECT 0.470000 100.295000 100.530000 100.915000 ;
      RECT 0.000000 96.545000 101.000000 100.295000 ;
      RECT 0.470000 95.925000 100.530000 96.545000 ;
      RECT 0.000000 84.955000 101.000000 95.925000 ;
      RECT 0.470000 84.335000 100.530000 84.955000 ;
      RECT 0.000000 80.585000 101.000000 84.335000 ;
      RECT 0.470000 79.965000 100.530000 80.585000 ;
      RECT 0.000000 68.805000 101.000000 79.965000 ;
      RECT 0.470000 68.185000 100.530000 68.805000 ;
      RECT 0.000000 64.625000 101.000000 68.185000 ;
      RECT 0.470000 64.005000 100.530000 64.625000 ;
      RECT 0.000000 52.845000 101.000000 64.005000 ;
      RECT 0.470000 52.225000 100.530000 52.845000 ;
      RECT 0.000000 48.665000 101.000000 52.225000 ;
      RECT 0.470000 48.045000 100.530000 48.665000 ;
      RECT 0.000000 36.885000 101.000000 48.045000 ;
      RECT 0.470000 36.265000 100.530000 36.885000 ;
      RECT 0.000000 32.515000 101.000000 36.265000 ;
      RECT 0.470000 31.895000 100.530000 32.515000 ;
      RECT 0.000000 20.925000 101.000000 31.895000 ;
      RECT 0.470000 20.305000 100.530000 20.925000 ;
      RECT 0.000000 16.555000 101.000000 20.305000 ;
      RECT 0.470000 15.935000 100.530000 16.555000 ;
      RECT 0.000000 4.965000 101.000000 15.935000 ;
      RECT 0.470000 4.345000 100.530000 4.965000 ;
      RECT 0.000000 0.000000 101.000000 4.345000 ;
    LAYER Metal10 ;
      RECT 98.050000 0.000000 101.000000 102.600000 ;
      RECT 90.050000 0.000000 91.150000 102.600000 ;
      RECT 82.050000 0.000000 83.150000 102.600000 ;
      RECT 74.050000 0.000000 75.150000 102.600000 ;
      RECT 66.050000 0.000000 67.150000 102.600000 ;
      RECT 58.050000 0.000000 59.150000 102.600000 ;
      RECT 50.050000 0.000000 51.150000 102.600000 ;
      RECT 42.050000 0.000000 43.150000 102.600000 ;
      RECT 34.050000 0.000000 35.150000 102.600000 ;
      RECT 26.050000 0.000000 27.150000 102.600000 ;
      RECT 18.050000 0.000000 19.150000 102.600000 ;
      RECT 10.050000 0.000000 11.150000 102.600000 ;
      RECT 0.000000 0.000000 3.150000 102.600000 ;
  END
END matmul_sync

END LIBRARY
